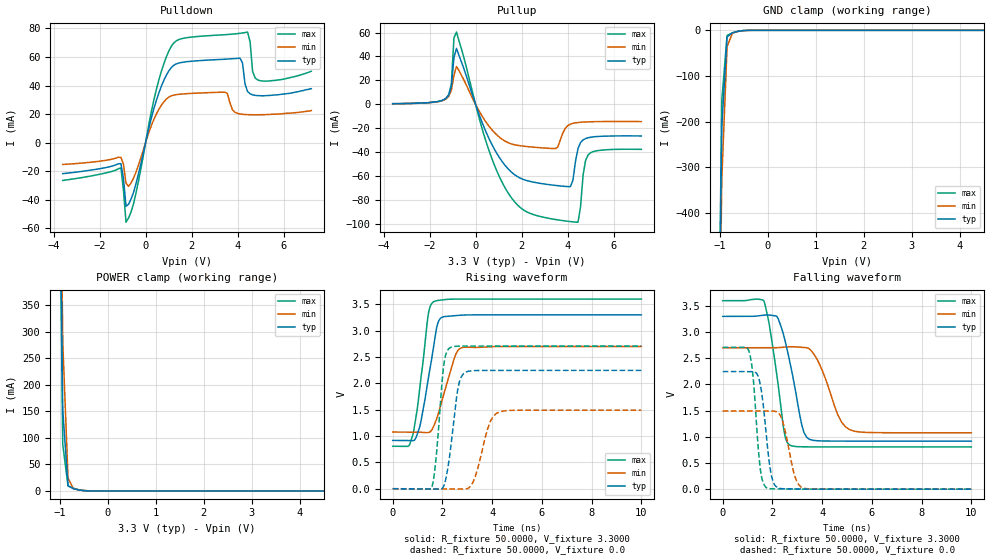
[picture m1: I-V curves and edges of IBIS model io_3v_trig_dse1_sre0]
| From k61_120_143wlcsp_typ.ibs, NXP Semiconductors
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[Model]  io_3v_trig_dse1_sre0
|   Model io_3v_trig_dse1_sre0
| Library cells for typ/min/max conditions are connected as defined below:
|  pad - External Pad
|  ipp_do_3v - Core Input
|  ipp_obe_3v - Output Buffer Enable
|  esd_boost - vdd_s_3v
|  esd_trigger - vss_s_3v
|  ipp_ame_3v - vss_s_3v
|  ipp_dse_3v - vdd_s_3v
|  ipp_ina_3v - NC
|  ipp_ina_mux_3v - NC
|  ipp_ind_3v - NC
|  ipp_pue_3v - vss_s_3v
|  ipp_sre_3v - vss_s_3v
|  tie_3v - vdd_s_3v
|  tie_hi - vdd_s_lv
|  vbuf_3v - vdd_s_3v
|  vdd_s_3v - vdd_s_3v
|  vdd_s_lv - vdd_s_lv
|  vss_bulk - vss_s_3v
|  vss_s_3v - vss_s_3v
| All other pins connected to ground
Model_type I/O
Polarity   Non-Inverting
Enable   Active-High
Vinl =   1.1550V
Vinh =   2.3100V
Vmeas =  1.6500V
Cref =   25.0000pF
Rref =   50.0000
Vref =   0.0V
C_comp   1.9033pF   1.7921pF   2.0562pF
[Temperature Range]   25.0000   0.1250k   -40.0000
[Voltage Range]   3.3000V   2.7000V   3.6000V
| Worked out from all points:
|   slope of the pulldown table from 0 to 0.495 V, typ, clamps not added: 16 ohm
|   slope of the pullup table from 0 to 0.495 V, typ, clamps not added: 19.9 ohm
|   GND clamp passes 1 mA (typ) near -0.54 V on its own axis
|   POWER clamp passes 1 mA (typ) near -0.53 V on its own axis
|   rising waveform, R_fixture 50.0000, V_fixture 3.3000: 20-80 % time 500ps typ, 595ps min, 420ps max; typ from 0.916 V to 3.3 V
|   rising waveform, R_fixture 50.0000, V_fixture 0.0: 20-80 % time 352ps typ, 496ps min, 276ps max; typ from 0 V to 2.25 V
|   falling waveform, R_fixture 50.0000, V_fixture 3.3000: 20-80 % time 594ps typ, 747ps min, 484ps max; typ from 3.3 V to 0.917 V
|   falling waveform, R_fixture 50.0000, V_fixture 0.0: 20-80 % time 311ps typ, 398ps min, 259ps max; typ from 2.25 V to 0 V
[Pulldown]
|Voltage   I(typ)   I(min)   I(max)
-3.6V     -21.69mA   -15.27mA   -26.46mA
-1.07V    -14.69mA   -10.32mA   -17.65mA
-850mV    -44.53mA   -28.35mA   -55.69mA
-520mV    -34.62mA   -24.72mA   -42.62mA
580mV     34.99mA    23.44mA    44.1mA
1.46V     55.81mA    33.87mA    72.31mA
3.44V     58.43mA    35.37mA    75.61mA
4.1V      59.15mA    20.09mA    76.57mA
4.43V     35.88mA    19.6mA     77.43mA
4.65V     33.46mA    19.5mA     49.92mA
4.87V     32.94mA    19.5mA     43.91mA
7.2V      37.8mA     22.5mA     50mA
[Pullup]
|Voltage   I(typ)   I(min)   I(max)
-3.6V     600uA      500uA      600uA
-1.27V    5.28mA     4.76mA     5.35mA
-1.05V    15.3mA     11.87mA    17.35mA
-940mV    39.22mA    24.2mA     55.5mA
-830mV    46.74mA    31.62mA    60.38mA
1.15V     -47.61mA   -29.08mA   -64.99mA
3.24V     -67.13mA   -36.73mA   -95.35mA
4.12V     -68.69mA   -16.52mA   -97.87mA
4.45V     -36.82mA   -15.12mA   -98.37mA
4.78V     -28.52mA   -14.66mA   -46.64mA
5V        -27.41mA   -14.5mA    -40.35mA
7.2V      -26.38mA   -14.35mA   -37.57mA
[GND_clamp]
|Voltage   I(typ)   I(min)   I(max)
-3.6V     -47.82A    -47.1A     -48.34A
-1.07V    -1.102A    -1.183A    -1.105A
-960mV    -210.7mA   -326mA     -154mA
-850mV    -14.47mA   -36.11mA   -11.11mA
-740mV    -5.262mA   -6.035mA   -5.843mA
-520mV    -636.9uA   -916uA     -467.5uA
-300mV    -2.578uA   -18.15uA   -370.9nA
7.2V      0A         0A         0A
[POWER_clamp]
|Voltage   I(typ)   I(min)   I(max)
-3.6V     36.98A     36.74A     37.19A
-1.05V    1.02A      1.161A     949.9mA
-940mV    152.3mA    280.6mA    87.35mA
-830mV    9.987mA    24.48mA    9.181mA
-720mV    4.227mA    4.409mA    5.116mA
-500mV    628.6uA    744.4uA    622.6uA
-390mV    66.57uA    164.1uA    29.9uA
7.2V      0A         0A         0A
[Ramp]
| variable   typ   min   max
dV/dt_r  1.3476/0.3518n   0.8948/0.4962n   1.6250/0.2756n
dV/dt_f  1.4298/0.5936n   0.9745/0.7466n   1.6761/0.4835n
R_load = 50.0000
[Rising Waveform]
R_fixture= 50.0000
V_fixture= 3.3000
V_fixture_min= 2.7000
V_fixture_max= 3.6000
|time   V(typ)   V(min)   V(max)
0s        916.5mV    1.075V     806.1mV
655.6ps   914.3mV    1.075V     817.1mV
816.4ps   912.4mV    1.076V     1.035V
1.097ns   1.192V     1.072V     1.946V
1.408ns   2.029V     1.066V     3.239V
1.649ns   2.723V     1.187V     3.551V
1.904ns   3.226V     1.541V     3.579V
2.479ns   3.283V     2.478V     3.599V
2.753ns   3.294V     2.673V     3.599V
10ns      3.3V       2.7V       3.6V
[Rising Waveform]
R_fixture= 50.0000
V_fixture= 0.0
V_fixture_min= 0.0
V_fixture_max= 0.0
|time   V(typ)   V(min)   V(max)
0s        2.009nV    208.9nV    1.41nV
1.573ns   -4.871mV   -1.881mV   29.97mV
1.723ns   -7.154mV   -2.504mV   480.4mV
2.064ns   65.73mV    -3.393mV   2.383V
2.334ns   784.5mV    -4.35mV    2.683V
2.608ns   1.862V     -4.528mV   2.705V
2.94ns    2.214V     -1.101mV   2.708V
3.306ns   2.243V     211.2mV    2.708V
4.187ns   2.245V     1.435V     2.708V
10ns      2.246V     1.491V     2.708V
[Falling Waveform]
R_fixture= 50.0000
V_fixture= 3.3000
V_fixture_min= 2.7000
V_fixture_max= 3.6000
|time   V(typ)   V(min)   V(max)
0s        3.3V       2.7V       3.6V
1.646ns   3.323V     2.7V       3.603V
2.22ns    3.267V     2.703V     2.032V
2.517ns   2.817V     2.715V     986mV
2.682ns   2.471V     2.72V      846.2mV
3.165ns   1.254V     2.708V     809.3mV
3.49ns    952.4mV    2.676V     808mV
4.627ns   918.4mV    1.423V     806.9mV
5.11ns    917.7mV    1.135V     806.7mV
10ns      917mV      1.076V     806.6mV
[Falling Waveform]
R_fixture= 50.0000
V_fixture= 0.0
V_fixture_min= 0.0
V_fixture_max= 0.0
|time   V(typ)   V(min)   V(max)
0s        2.246V     1.492V     2.709V
1.053ns   2.247V     1.492V     2.643V
1.201ns   2.247V     1.492V     2.25V
1.492ns   2.043V     1.492V     466.6mV
1.756ns   1.018V     1.493V     28.76mV
2.108ns   70.01mV    1.485V     5.423mV
2.385ns   9.554mV    1.335V     3.5mV
2.896ns   4.242mV    251.8mV    676.8uV
3.215ns   1.889mV    24.3mV     444.4uV
10ns      246uV      205.5uV    266.9uV
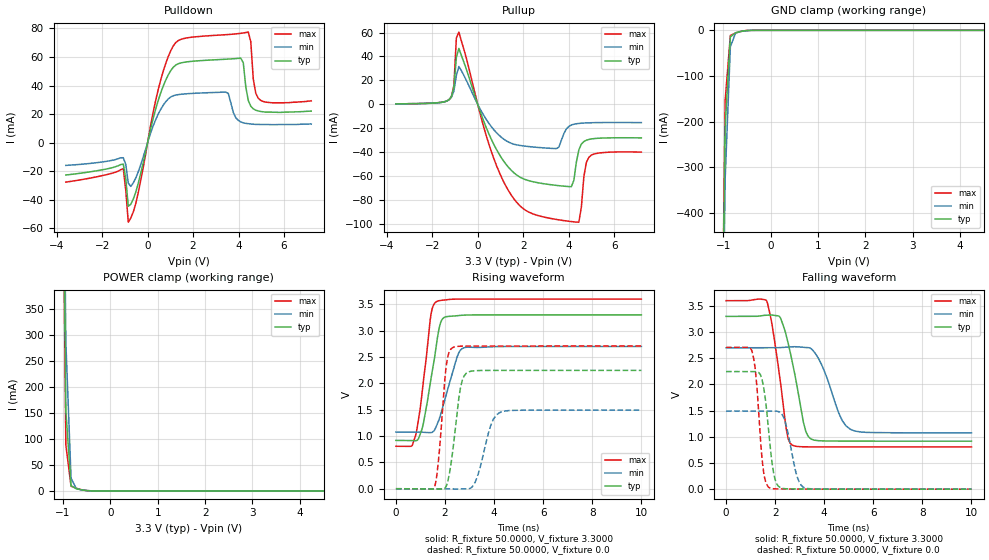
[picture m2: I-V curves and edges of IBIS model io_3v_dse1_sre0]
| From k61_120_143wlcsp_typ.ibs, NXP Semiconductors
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[Model]  io_3v_dse1_sre0
|   Model io_3v_dse1_sre0
| Library cells for typ/min/max conditions are connected as defined below:
|  pad - External Pad
|  ipp_do_3v - Core Input
|  ipp_obe_3v - Output Buffer Enable
|  esd_boost - vdd_s_3v
|  esd_trigger - vss_s_3v
|  ipp_ame_3v - vss_s_3v
|  ipp_dse_3v - vdd_s_3v
|  ipp_ina_3v - NC
|  ipp_ina_mux_3v - NC
|  ipp_ind_3v - NC
|  ipp_pue_3v - vss_s_3v
|  ipp_sre_3v - vss_s_3v
|  tie_3v - vdd_s_3v
|  tie_hi - vdd_s_lv
|  vbuf_3v - vdd_s_3v
|  vdd_s_3v - vdd_s_3v
|  vdd_s_lv - vdd_s_lv
|  vss_bulk - vss_s_3v
|  vss_s_3v - vss_s_3v
| All other pins connected to ground
Model_type I/O
Polarity   Non-Inverting
Enable   Active-High
Vinl =   1.1550V
Vinh =   2.3100V
Vmeas =  1.6500V
Cref =   25.0000pF
Rref =   50.0000
Vref =   0.0V
C_comp   1.9040pF   1.7928pF   2.0571pF
[Temperature Range]   25.0000   0.1250k   -40.0000
[Voltage Range]   3.3000V   2.7000V   3.6000V
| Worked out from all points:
|   slope of the pulldown table from 0 to 0.495 V, typ, clamps not added: 16 ohm
|   slope of the pullup table from 0 to 0.495 V, typ, clamps not added: 19.9 ohm
|   GND clamp passes 1 mA (typ) near -0.54 V on its own axis
|   POWER clamp passes 1 mA (typ) near -0.53 V on its own axis
|   rising waveform, R_fixture 50.0000, V_fixture 3.3000: 20-80 % time 498ps typ, 592ps min, 417ps max; typ from 0.916 V to 3.3 V
|   rising waveform, R_fixture 50.0000, V_fixture 0.0: 20-80 % time 352ps typ, 493ps min, 278ps max; typ from 0 V to 2.25 V
|   falling waveform, R_fixture 50.0000, V_fixture 3.3000: 20-80 % time 593ps typ, 750ps min, 483ps max; typ from 3.3 V to 0.917 V
|   falling waveform, R_fixture 50.0000, V_fixture 0.0: 20-80 % time 309ps typ, 400ps min, 259ps max; typ from 2.25 V to 0 V
[Pulldown]
|Voltage   I(typ)   I(min)   I(max)
-3.6V     -22.64mA   -15.93mA   -27.64mA
-1.07V    -15.06mA   -10.57mA   -18.14mA
-850mV    -44.54mA   -28.36mA   -55.71mA
-520mV    -34.63mA   -24.73mA   -42.63mA
580mV     35mA       23.45mA    44.11mA
1.46V     55.82mA    33.88mA    72.32mA
3.44V     58.43mA    35.37mA    75.62mA
4.1V      59.16mA    14.53mA    76.58mA
4.43V     29.52mA    13.3mA     77.44mA
4.65V     23.68mA    12.9mA     44.58mA
4.87V     22.2mA     12.8mA     31.08mA
7.2V      22.1mA     13mA       29.3mA
[Pullup]
|Voltage   I(typ)   I(min)   I(max)
-3.6V     400uA      400uA      500uA
-1.27V    3.86mA     3.67mA     3.76mA
-1.05V    14.15mA    11.16mA    15.69mA
-940mV    39.2mA     24.13mA    55.51mA
-830mV    46.74mA    31.62mA    60.38mA
1.15V     -47.61mA   -29.08mA   -64.99mA
3.13V     -66.86mA   -36.61mA   -94.95mA
4.12V     -68.7mA    -17.24mA   -97.87mA
4.45V     -37.93mA   -15.9mA    -98.38mA
4.78V     -29.93mA   -15.45mA   -48.43mA
5V        -28.86mA   -15.32mA   -42.37mA
7.2V      -27.98mA   -15.22mA   -39.85mA
[GND_clamp]
|Voltage   I(typ)   I(min)   I(max)
-3.6V     -47.78A    -47.06A    -48.3A
-1.07V    -1.101A    -1.183A    -1.105A
-960mV    -210.7mA   -326mA     -154mA
-850mV    -14.47mA   -36.11mA   -11.11mA
-740mV    -5.262mA   -6.035mA   -5.843mA
-520mV    -637uA     -916uA     -467.5uA
-300mV    -2.578uA   -18.15uA   -370.9nA
7.2V      0A         0A         0A
[POWER_clamp]
|Voltage   I(typ)   I(min)   I(max)
-3.6V     52.51A     51.88A     52.98A
-1.05V    1.126A     1.265A     1.065A
-940mV    154.2mA    286.1mA    88.03mA
-830mV    9.989mA    24.5mA     9.181mA
-720mV    4.227mA    4.409mA    5.116mA
-390mV    66.57uA    164.1uA    29.9uA
7.2V      0A         0A         0A
[Ramp]
| variable   typ   min   max
dV/dt_r  1.3476/0.3516n   0.8948/0.4927n   1.6250/0.2777n
dV/dt_f  1.4299/0.5927n   0.9746/0.7497n   1.6762/0.4828n
R_load = 50.0000
[Rising Waveform]
R_fixture= 50.0000
V_fixture= 3.3000
V_fixture_min= 2.7000
V_fixture_max= 3.6000
|time   V(typ)   V(min)   V(max)
0s        916.3mV    1.075V     805.9mV
621.7ps   914.8mV    1.075V     805.5mV
792.1ps   911.7mV    1.076V     993.8mV
1.076ns   1.155V     1.073V     1.867V
1.43ns    2.093V     1.067V     3.313V
1.67ns    2.797V     1.211V     3.556V
1.907ns   3.229V     1.548V     3.579V
2.497ns   3.284V     2.507V     3.599V
2.749ns   3.294V     2.672V     3.599V
10ns      3.3V       2.7V       3.6V
[Rising Waveform]
R_fixture= 50.0000
V_fixture= 0.0
V_fixture_min= 0.0
V_fixture_max= 0.0
|time   V(typ)   V(min)   V(max)
0s        2.009nV    208.9nV    1.41nV
1.567ns   -4.799mV   -1.781mV   24.52mV
1.753ns   -6.838mV   -2.436mV   626.9mV
2.042ns   42.34mV    -3.404mV   2.304V
2.293ns   631.6mV    -4.18mV    2.673V
2.628ns   1.913V     -4.197mV   2.705V
2.964ns   2.219V     -204.6uV   2.708V
3.255ns   2.241V     151.3mV    2.708V
4.226ns   2.245V     1.445V     2.708V
10ns      2.246V     1.491V     2.708V
[Falling Waveform]
R_fixture= 50.0000
V_fixture= 3.3000
V_fixture_min= 2.7000
V_fixture_max= 3.6000
|time   V(typ)   V(min)   V(max)
0s        3.3V       2.7V       3.6V
1.652ns   3.324V     2.7V       3.6V
1.875ns   3.325V     2.7V       3.141V
2.223ns   3.263V     2.704V     2.02V
2.455ns   2.932V     2.713V     1.136V
2.7ns     2.427V     2.72V      840.5mV
3.149ns   1.285V     2.709V     809.3mV
3.466ns   957mV      2.682V     807.9mV
5.058ns   917.6mV    1.145V     806.6mV
10ns      916.8mV    1.076V     806.4mV
[Falling Waveform]
R_fixture= 50.0000
V_fixture= 0.0
V_fixture_min= 0.0
V_fixture_max= 0.0
|time   V(typ)   V(min)   V(max)
0s        2.246V     1.492V     2.709V
1.042ns   2.247V     1.492V     2.655V
1.236ns   2.244V     1.492V     2.08V
1.465ns   2.096V     1.492V     590mV
1.751ns   1.039V     1.493V     30.59mV
1.932ns   323.6mV    1.494V     8.049mV
2.101ns   74.34mV    1.487V     5.55mV
2.413ns   8.603mV    1.283V     3.29mV
3.2ns     1.968mV    25.81mV    451.3uV
10ns      245.8uV    202.1uV    266.6uV
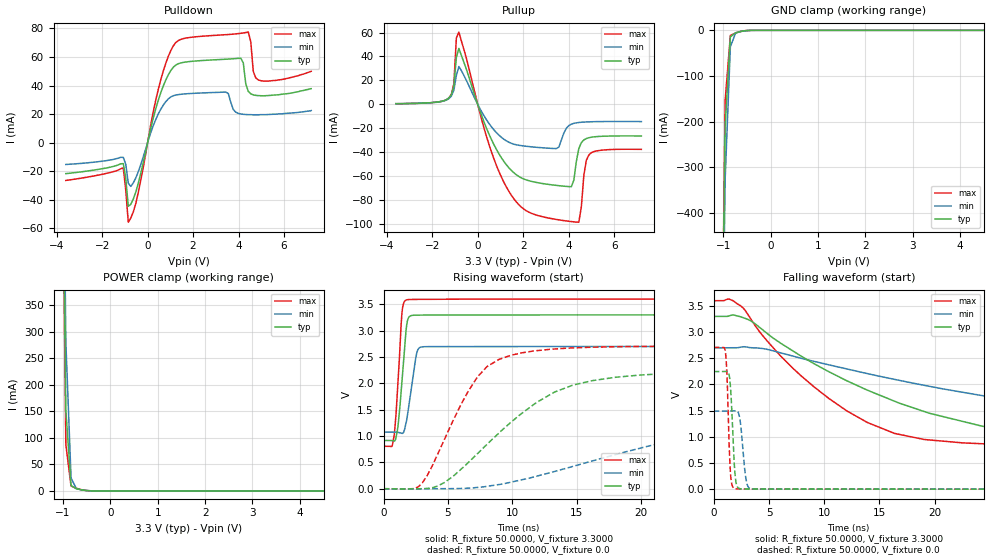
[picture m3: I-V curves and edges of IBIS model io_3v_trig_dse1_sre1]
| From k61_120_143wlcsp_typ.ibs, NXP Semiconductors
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[Model]  io_3v_trig_dse1_sre1
|   Model io_3v_trig_dse1_sre1
| Library cells for typ/min/max conditions are connected as defined below:
|  pad - External Pad
|  ipp_do_3v - Core Input
|  ipp_obe_3v - Output Buffer Enable
|  esd_boost - vdd_s_3v
|  esd_trigger - vss_s_3v
|  ipp_ame_3v - vss_s_3v
|  ipp_dse_3v - vdd_s_3v
|  ipp_ina_3v - NC
|  ipp_ina_mux_3v - NC
|  ipp_ind_3v - NC
|  ipp_pue_3v - vss_s_3v
|  ipp_sre_3v - vdd_s_3v
|  tie_3v - vdd_s_3v
|  tie_hi - vdd_s_lv
|  vbuf_3v - vdd_s_3v
|  vdd_s_3v - vdd_s_3v
|  vdd_s_lv - vdd_s_lv
|  vss_bulk - vss_s_3v
|  vss_s_3v - vss_s_3v
| All other pins connected to ground
Model_type I/O
Polarity   Non-Inverting
Enable   Active-High
Vinl =   1.1550V
Vinh =   2.3100V
Vmeas =  1.6500V
Cref =   25.0000pF
Rref =   50.0000
Vref =   0.0V
C_comp   1.9033pF   1.7921pF   2.0562pF
[Temperature Range]   25.0000   0.1250k   -40.0000
[Voltage Range]   3.3000V   2.7000V   3.6000V
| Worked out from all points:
|   slope of the pulldown table from 0 to 0.495 V, typ, clamps not added: 16 ohm
|   slope of the pullup table from 0 to 0.495 V, typ, clamps not added: 19.9 ohm
|   GND clamp passes 1 mA (typ) near -0.54 V on its own axis
|   POWER clamp passes 1 mA (typ) near -0.53 V on its own axis
|   rising waveform, R_fixture 50.0000, V_fixture 3.3000: 20-80 % time 477ps typ, 574ps min, 395ps max; typ from 0.916 V to 3.3 V
|   rising waveform, R_fixture 50.0000, V_fixture 0.0: 20-80 % time 6.64ns typ, 16ns min, 3.47ns max; typ from 0 V to 2.25 V
|   falling waveform, R_fixture 50.0000, V_fixture 3.3000: 20-80 % time 14.8ns typ, 28.6ns min, 9.11ns max; typ from 3.3 V to 0.916 V
|   falling waveform, R_fixture 50.0000, V_fixture 0.0: 20-80 % time 304ps typ, 395ps min, 253ps max; typ from 2.25 V to 0 V
[Pulldown]
|Voltage   I(typ)   I(min)   I(max)
-3.6V     -21.69mA   -15.27mA   -26.46mA
-1.07V    -14.69mA   -10.32mA   -17.65mA
-850mV    -44.53mA   -28.35mA   -55.69mA
-520mV    -34.62mA   -24.72mA   -42.62mA
580mV     34.99mA    23.44mA    44.1mA
1.46V     55.81mA    33.87mA    72.31mA
3.44V     58.43mA    35.36mA    75.61mA
4.1V      59.15mA    20.09mA    76.57mA
4.43V     35.88mA    19.6mA     77.43mA
4.65V     33.46mA    19.5mA     49.92mA
4.87V     32.94mA    19.5mA     43.91mA
7.2V      37.8mA     22.5mA     50mA
[Pullup]
|Voltage   I(typ)   I(min)   I(max)
-3.6V     600uA      500uA      600uA
-1.27V    5.28mA     4.76mA     5.35mA
-1.05V    15.3mA     11.87mA    17.35mA
-940mV    39.22mA    24.2mA     55.5mA
-830mV    46.74mA    31.62mA    60.38mA
1.15V     -47.61mA   -29.08mA   -64.99mA
3.24V     -67.13mA   -36.73mA   -95.35mA
4.12V     -68.69mA   -16.52mA   -97.87mA
4.45V     -36.82mA   -15.12mA   -98.37mA
4.78V     -28.52mA   -14.66mA   -46.64mA
5V        -27.41mA   -14.5mA    -40.35mA
7.2V      -26.38mA   -14.35mA   -37.57mA
[GND_clamp]
|Voltage   I(typ)   I(min)   I(max)
-3.6V     -47.82A    -47.1A     -48.34A
-1.07V    -1.102A    -1.183A    -1.105A
-960mV    -210.7mA   -326mA     -154mA
-850mV    -14.47mA   -36.11mA   -11.11mA
-740mV    -5.262mA   -6.035mA   -5.843mA
-520mV    -636.9uA   -916uA     -467.5uA
-300mV    -2.578uA   -18.15uA   -370.9nA
7.2V      0A         0A         0A
[POWER_clamp]
|Voltage   I(typ)   I(min)   I(max)
-3.6V     36.98A     36.74A     37.19A
-1.05V    1.02A      1.161A     949.9mA
-940mV    152.3mA    280.6mA    87.35mA
-830mV    9.987mA    24.48mA    9.181mA
-720mV    4.227mA    4.409mA    5.116mA
-500mV    628.6uA    744.4uA    622.6uA
-390mV    66.57uA    164.1uA    29.9uA
7.2V      0A         0A         0A
[Ramp]
| variable   typ   min   max
dV/dt_r  1.3478/6.6433n   0.8951/15.9651n   1.6252/3.4740n
dV/dt_f  1.4301/14.8115n   0.9748/28.5903n   1.6764/9.1110n
R_load = 50.0000
[Rising Waveform]
R_fixture= 50.0000
V_fixture= 3.3000
V_fixture_min= 2.7000
V_fixture_max= 3.6000
|time   V(typ)   V(min)   V(max)
0s        916.5mV    1.075V     806.1mV
650.6ps   913mV      1.075V     805mV
931.5ps   941.1mV    1.075V     1.321V
1.123ns   1.202V     1.069V     2.075V
1.446ns   2.116V     1.05V      3.391V
1.777ns   3.084V     1.287V     3.584V
2.039ns   3.275V     1.715V     3.592V
2.624ns   3.295V     2.618V     3.594V
3.319ns   3.296V     2.697V     3.596V
250ns     3.3V       2.7V       3.6V
[Rising Waveform]
R_fixture= 50.0000
V_fixture= 0.0
V_fixture_min= 0.0
V_fixture_max= 0.0
|time   V(typ)   V(min)   V(max)
0s        2.009nV    208.9nV    1.41nV
3.009ns   -219.1uV   -587uV     112mV
4.711ns   115.5mV    -134.9uV   928.5mV
6.575ns   496.1mV    10.62mV    1.85V
8.035ns   842.2mV    45.24mV    2.318V
11.88ns   1.637V     236.6mV    2.62V
14.36ns   1.934V     399.2mV    2.669V
28.19ns   2.227V     1.175V     2.708V
47.72ns   2.246V     1.454V     2.709V
250ns     2.246V     1.492V     2.709V
[Falling Waveform]
R_fixture= 50.0000
V_fixture= 3.3000
V_fixture_min= 2.7000
V_fixture_max= 3.6000
|time   V(typ)   V(min)   V(max)
0s        3.3V       2.7V       3.6V
2.461ns   3.291V     2.714V     3.498V
7.044ns   2.656V     2.549V     2.333V
12.05ns   2.07V      2.296V     1.495V
16.36ns   1.681V     2.098V     1.065V
22.52ns   1.295V     1.851V     884.6mV
33.62ns   1V         1.512V     822.6mV
50.17ns   932.6mV    1.236V     808.3mV
68.28ns   919.6mV    1.128V     806.3mV
250ns     916.5mV    1.075V     806.1mV
[Falling Waveform]
R_fixture= 50.0000
V_fixture= 0.0
V_fixture_min= 0.0
V_fixture_max= 0.0
|time   V(typ)   V(min)   V(max)
0s        2.246V     1.492V     2.709V
1.039ns   2.248V     1.492V     2.646V
1.215ns   2.248V     1.491V     2.075V
1.383ns   2.193V     1.492V     904.8mV
1.579ns   1.732V     1.493V     152.8mV
1.894ns   356.7mV    1.497V     10.97mV
2.096ns   61.58mV    1.493V     5.077mV
2.977ns   3.283mV    126.5mV    1.844mV
3.602ns   1.859mV    3.488mV    1.169mV
250ns     -5.291nV   200.6nV    -4.024nV
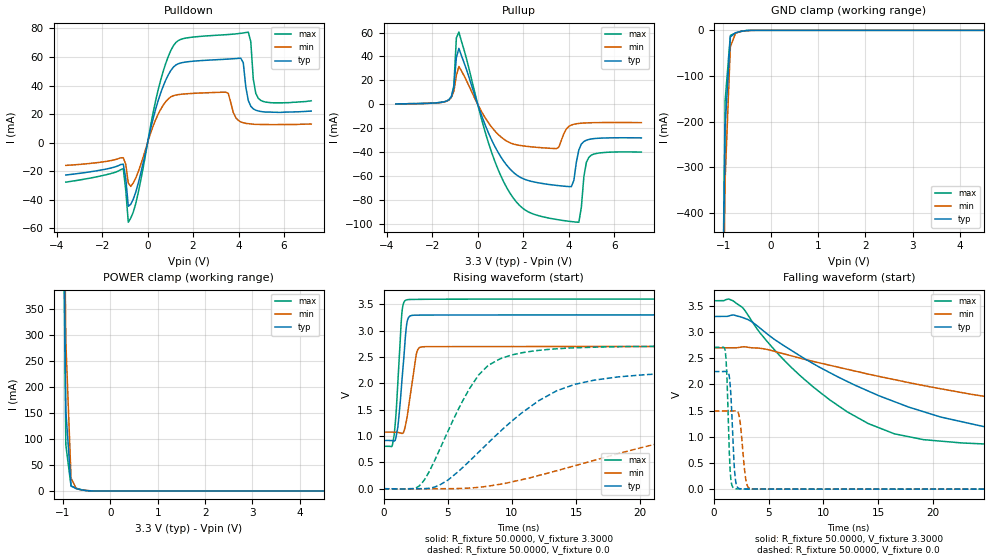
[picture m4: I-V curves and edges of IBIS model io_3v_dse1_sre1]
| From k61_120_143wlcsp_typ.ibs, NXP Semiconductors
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[Model]  io_3v_dse1_sre1
|   Model io_3v_dse1_sre1
| Library cells for typ/min/max conditions are connected as defined below:
|  pad - External Pad
|  ipp_do_3v - Core Input
|  ipp_obe_3v - Output Buffer Enable
|  esd_boost - vdd_s_3v
|  esd_trigger - vss_s_3v
|  ipp_ame_3v - vss_s_3v
|  ipp_dse_3v - vdd_s_3v
|  ipp_ina_3v - NC
|  ipp_ina_mux_3v - NC
|  ipp_ind_3v - NC
|  ipp_pue_3v - vss_s_3v
|  ipp_sre_3v - vdd_s_3v
|  tie_3v - vdd_s_3v
|  tie_hi - vdd_s_lv
|  vbuf_3v - vdd_s_3v
|  vdd_s_3v - vdd_s_3v
|  vdd_s_lv - vdd_s_lv
|  vss_bulk - vss_s_3v
|  vss_s_3v - vss_s_3v
| All other pins connected to ground
Model_type I/O
Polarity   Non-Inverting
Enable   Active-High
Vinl =   1.1550V
Vinh =   2.3100V
Vmeas =  1.6500V
Cref =   25.0000pF
Rref =   50.0000
Vref =   0.0V
C_comp   1.9040pF   1.7928pF   2.0571pF
[Temperature Range]   25.0000   0.1250k   -40.0000
[Voltage Range]   3.3000V   2.7000V   3.6000V
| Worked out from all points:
|   slope of the pulldown table from 0 to 0.495 V, typ, clamps not added: 16 ohm
|   slope of the pullup table from 0 to 0.495 V, typ, clamps not added: 19.9 ohm
|   GND clamp passes 1 mA (typ) near -0.54 V on its own axis
|   POWER clamp passes 1 mA (typ) near -0.53 V on its own axis
|   rising waveform, R_fixture 50.0000, V_fixture 3.3000: 20-80 % time 474ps typ, 573ps min, 392ps max; typ from 0.916 V to 3.3 V
|   rising waveform, R_fixture 50.0000, V_fixture 0.0: 20-80 % time 6.66ns typ, 16ns min, 3.45ns max; typ from 0 V to 2.25 V
|   falling waveform, R_fixture 50.0000, V_fixture 3.3000: 20-80 % time 14.7ns typ, 28.4ns min, 9.12ns max; typ from 3.3 V to 0.916 V
|   falling waveform, R_fixture 50.0000, V_fixture 0.0: 20-80 % time 303ps typ, 390ps min, 251ps max; typ from 2.25 V to 0 V
[Pulldown]
|Voltage   I(typ)   I(min)   I(max)
-3.6V     -22.64mA   -15.93mA   -27.64mA
-1.07V    -15.06mA   -10.57mA   -18.14mA
-850mV    -44.54mA   -28.36mA   -55.71mA
-520mV    -34.63mA   -24.73mA   -42.63mA
580mV     35mA       23.45mA    44.11mA
1.46V     55.82mA    33.87mA    72.32mA
3.44V     58.43mA    35.37mA    75.62mA
4.1V      59.16mA    14.52mA    76.58mA
4.43V     29.52mA    13.3mA     77.44mA
4.65V     23.68mA    12.9mA     44.58mA
4.87V     22.2mA     12.8mA     31.08mA
7.2V      22.1mA     13mA       29.3mA
[Pullup]
|Voltage   I(typ)   I(min)   I(max)
-3.6V     400uA      400uA      500uA
-1.27V    3.86mA     3.67mA     3.76mA
-1.05V    14.15mA    11.16mA    15.69mA
-940mV    39.2mA     24.13mA    55.51mA
-830mV    46.74mA    31.62mA    60.38mA
1.15V     -47.61mA   -29.08mA   -64.99mA
3.13V     -66.86mA   -36.61mA   -94.95mA
4.12V     -68.7mA    -17.24mA   -97.87mA
4.45V     -37.93mA   -15.9mA    -98.38mA
4.78V     -29.93mA   -15.45mA   -48.43mA
5V        -28.86mA   -15.31mA   -42.37mA
7.2V      -27.98mA   -15.22mA   -39.85mA
[GND_clamp]
|Voltage   I(typ)   I(min)   I(max)
-3.6V     -47.78A    -47.06A    -48.3A
-1.07V    -1.101A    -1.183A    -1.105A
-960mV    -210.7mA   -326mA     -154mA
-850mV    -14.47mA   -36.11mA   -11.11mA
-740mV    -5.262mA   -6.035mA   -5.843mA
-520mV    -637uA     -916uA     -467.5uA
-300mV    -2.578uA   -18.15uA   -370.9nA
7.2V      0A         0A         0A
[POWER_clamp]
|Voltage   I(typ)   I(min)   I(max)
-3.6V     52.51A     51.88A     52.98A
-1.05V    1.126A     1.265A     1.065A
-940mV    154.2mA    286.1mA    88.03mA
-830mV    9.989mA    24.5mA     9.181mA
-720mV    4.227mA    4.409mA    5.116mA
-390mV    66.57uA    164.1uA    29.9uA
7.2V      0A         0A         0A
[Ramp]
| variable   typ   min   max
dV/dt_r  1.3478/6.6600n   0.8951/16.0012n   1.6252/3.4473n
dV/dt_f  1.4302/14.6691n   0.9749/28.4435n   1.6765/9.1203n
R_load = 50.0000
[Rising Waveform]
R_fixture= 50.0000
V_fixture= 3.3000
V_fixture_min= 2.7000
V_fixture_max= 3.6000
|time   V(typ)   V(min)   V(max)
0s        916.3mV    1.075V     805.9mV
678.6ps   911.9mV    1.076V     821.6mV
948.9ps   960.7mV    1.075V     1.368V
1.142ns   1.248V     1.069V     2.149V
1.44ns    2.104V     1.048V     3.383V
1.773ns   3.082V     1.282V     3.584V
2.015ns   3.271V     1.675V     3.592V
2.591ns   3.295V     2.594V     3.594V
3.273ns   3.296V     2.696V     3.596V
250ns     3.3V       2.7V       3.6V
[Rising Waveform]
R_fixture= 50.0000
V_fixture= 0.0
V_fixture_min= 0.0
V_fixture_max= 0.0
|time   V(typ)   V(min)   V(max)
0s        2.009nV    208.9nV    1.41nV
2.888ns   -686.6uV   -942.1uV   78.44mV
5.004ns   162.9mV    201.7uV    1.087V
6.684ns   521.6mV    12.22mV    1.896V
8.154ns   871mV      49.22mV    2.341V
12.1ns    1.672V     250.4mV    2.626V
14.44ns   1.941V     405.3mV    2.67V
27.7ns    2.225V     1.157V     2.708V
46.86ns   2.246V     1.45V      2.709V
250ns     2.246V     1.492V     2.709V
[Falling Waveform]
R_fixture= 50.0000
V_fixture= 3.3000
V_fixture_min= 2.7000
V_fixture_max= 3.6000
|time   V(typ)   V(min)   V(max)
0s        3.3V       2.7V       3.6V
1.383ns   3.309V     2.7V       3.631V
2.462ns   3.291V     2.714V     3.497V
7.003ns   2.661V     2.551V     2.34V
12.17ns   2.058V     2.289V     1.478V
16.47ns   1.673V     2.093V     1.058V
22.63ns   1.288V     1.846V     883.1mV
34.5ns    992.2mV    1.491V     821mV
65.83ns   920.4mV    1.137V     806.1mV
250ns     916.3mV    1.075V     805.9mV
[Falling Waveform]
R_fixture= 50.0000
V_fixture= 0.0
V_fixture_min= 0.0
V_fixture_max= 0.0
|time   V(typ)   V(min)   V(max)
0s        2.246V     1.492V     2.709V
1.03ns    2.248V     1.492V     2.658V
1.2ns     2.248V     1.491V     2.159V
1.392ns   2.184V     1.492V     849.6mV
1.608ns   1.619V     1.493V     116.7mV
1.837ns   544.9mV    1.496V     16.25mV
2.079ns   71.93mV    1.495V     5.402mV
2.932ns   3.505mV    173.4mV    1.976mV
3.597ns   1.905mV    3.625mV    1.19mV
250ns     -5.298nV   200.5nV    -4.023nV
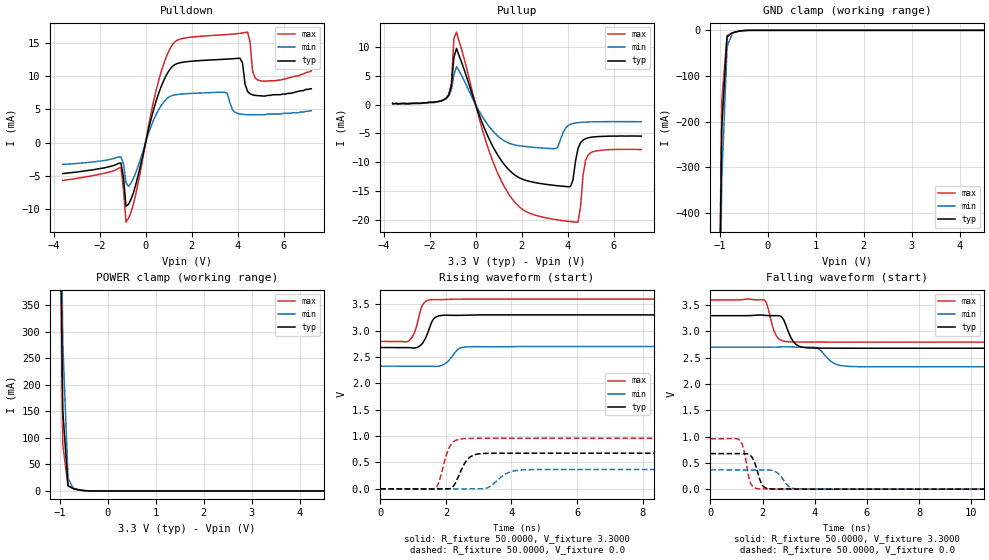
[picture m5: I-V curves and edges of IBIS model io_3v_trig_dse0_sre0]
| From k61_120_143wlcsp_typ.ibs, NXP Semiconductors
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[Model]  io_3v_trig_dse0_sre0
|   Model io_3v_trig_dse0_sre0
| Library cells for typ/min/max conditions are connected as defined below:
|  pad - External Pad
|  ipp_do_3v - Core Input
|  ipp_obe_3v - Output Buffer Enable
|  esd_boost - vdd_s_3v
|  esd_trigger - vss_s_3v
|  ipp_ame_3v - vss_s_3v
|  ipp_dse_3v - vss_s_3v
|  ipp_ina_3v - NC
|  ipp_ina_mux_3v - NC
|  ipp_ind_3v - NC
|  ipp_pue_3v - vss_s_3v
|  ipp_sre_3v - vss_s_3v
|  tie_3v - vdd_s_3v
|  tie_hi - vdd_s_lv
|  vbuf_3v - vdd_s_3v
|  vdd_s_3v - vdd_s_3v
|  vdd_s_lv - vdd_s_lv
|  vss_bulk - vss_s_3v
|  vss_s_3v - vss_s_3v
| All other pins connected to ground
Model_type I/O
Polarity   Non-Inverting
Enable   Active-High
Vinl =   1.1550V
Vinh =   2.3100V
Vmeas =  1.6500V
Cref =   25.0000pF
Rref =   50.0000
Vref =   0.0V
C_comp   1.9033pF   1.7921pF   2.0562pF
[Temperature Range]   25.0000   0.1250k   -40.0000
[Voltage Range]   3.3000V   2.7000V   3.6000V
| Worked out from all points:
|   slope of the pulldown table from 0 to 0.495 V, typ, clamps not added: 74.6 ohm
|   slope of the pullup table from 0 to 0.495 V, typ, clamps not added: 96.1 ohm
|   GND clamp passes 1 mA (typ) near -0.54 V on its own axis
|   POWER clamp passes 1 mA (typ) near -0.53 V on its own axis
|   rising waveform, R_fixture 50.0000, V_fixture 3.3000: 20-80 % time 249ps typ, 295ps min, 218ps max; typ from 2.68 V to 3.3 V
|   rising waveform, R_fixture 50.0000, V_fixture 0.0: 20-80 % time 324ps typ, 446ps min, 273ps max; typ from 0 V to 0.676 V
|   falling waveform, R_fixture 50.0000, V_fixture 3.3000: 20-80 % time 336ps typ, 464ps min, 278ps max; typ from 3.3 V to 2.68 V
|   falling waveform, R_fixture 50.0000, V_fixture 0.0: 20-80 % time 264ps typ, 346ps min, 219ps max; typ from 0.676 V to 0 V
[Pulldown]
|Voltage   I(typ)   I(min)   I(max)
-3.6V     -4.64mA    -3.27mA    -5.68mA
-1.07V    -3.05mA    -2.138mA   -3.686mA
-850mV    -9.531mA   -6.04mA    -11.94mA
-520mV    -7.433mA   -5.304mA   -9.157mA
580mV     7.512mA    5.028mA    9.473mA
1.46V     11.97mA    7.26mA     15.51mA
3.44V     12.53mA    7.58mA     16.21mA
4.1V      12.68mA    4.3mA      16.42mA
4.43V     7.69mA     4.2mA      16.6mA
4.65V     7.17mA     4.2mA      10.69mA
4.87V     7.06mA     4.2mA      9.41mA
7.2V      8.1mA      4.8mA      10.8mA
[Pullup]
|Voltage   I(typ)   I(min)   I(max)
-3.6V     200uA      100uA      200uA
-1.27V    1.12mA     1.01mA     1.13mA
-1.05V    3.27mA     2.54mA     3.696mA
-940mV    8.16mA     5.079mA    11.47mA
-830mV    9.694mA    6.562mA    12.52mA
1.15V     -9.866mA   -6.026mA   -13.47mA
3.24V     -13.9mA    -7.609mA   -19.73mA
4.12V     -14.22mA   -3.42mA    -20.25mA
4.45V     -7.608mA   -3.13mA    -20.35mA
4.78V     -5.902mA   -3.04mA    -9.632mA
5V        -5.67mA    -3mA       -8.343mA
7.2V      -5.46mA    -2.98mA    -7.78mA
[GND_clamp]
|Voltage   I(typ)   I(min)   I(max)
-3.6V     -47.82A    -47.1A     -48.34A
-1.07V    -1.102A    -1.183A    -1.105A
-960mV    -210.7mA   -326mA     -154mA
-850mV    -14.47mA   -36.11mA   -11.11mA
-740mV    -5.262mA   -6.035mA   -5.843mA
-520mV    -636.9uA   -916uA     -467.5uA
-300mV    -2.578uA   -18.15uA   -370.9nA
7.2V      0A         0A         0A
[POWER_clamp]
|Voltage   I(typ)   I(min)   I(max)
-3.6V     36.98A     36.74A     37.19A
-1.05V    1.02A      1.161A     949.9mA
-940mV    152.3mA    280.6mA    87.35mA
-830mV    9.987mA    24.48mA    9.181mA
-720mV    4.227mA    4.409mA    5.116mA
-500mV    628.6uA    744.4uA    622.6uA
-390mV    66.57uA    164.1uA    29.9uA
7.2V      0A         0A         0A
[Ramp]
| variable   typ   min   max
dV/dt_r  0.4057/0.3234n   0.2199/0.4457n   0.5756/0.2727n
dV/dt_f  0.3715/0.3360n   0.2234/0.4635n   0.4821/0.2780n
R_load = 50.0000
[Rising Waveform]
R_fixture= 50.0000
V_fixture= 3.3000
V_fixture_min= 2.7000
V_fixture_max= 3.6000
|time   V(typ)   V(min)   V(max)
0s        2.681V     2.328V     2.796V
881.7ps   2.678V     2.328V     2.812V
1.026ns   2.672V     2.328V     2.94V
1.299ns   2.77V      2.327V     3.498V
1.593ns   3.192V     2.322V     3.59V
1.709ns   3.263V     2.321V     3.588V
1.932ns   3.292V     2.355V     3.589V
2.402ns   3.291V     2.661V     3.599V
2.708ns   3.297V     2.696V     3.599V
20ns      3.3V       2.7V       3.6V
[Rising Waveform]
R_fixture= 50.0000
V_fixture= 0.0
V_fixture_min= 0.0
V_fixture_max= 0.0
|time   V(typ)   V(min)   V(max)
0s        5.332nV    489.5nV    4.027nV
1.688ns   -2.656mV   -95.5uV    13.65mV
2.13ns    5.672mV    -2.28mV    818.1mV
2.511ns   412.6mV    -1.555mV   950.9mV
2.73ns    601.7mV    -468.2uV   956.6mV
2.994ns   663.2mV    -701.5uV   958.2mV
3.338ns   674.2mV    40.47mV    958.6mV
3.908ns   675.6mV    309.8mV    958.8mV
4.482ns   675.8mV    363.1mV    958.9mV
20ns      676.2mV    366.5mV    959.4mV
[Falling Waveform]
R_fixture= 50.0000
V_fixture= 3.3000
V_fixture_min= 2.7000
V_fixture_max= 3.6000
|time   V(typ)   V(min)   V(max)
0s        3.3V       2.7V       3.6V
2.059ns   3.307V     2.7V       3.599V
2.542ns   3.3V       2.703V     2.907V
2.728ns   3.282V     2.705V     2.829V
3.008ns   2.971V     2.708V     2.803V
3.41ns    2.715V     2.701V     2.799V
4.115ns   2.683V     2.681V     2.797V
4.675ns   2.682V     2.412V     2.797V
5.235ns   2.681V     2.337V     2.797V
20ns      2.681V     2.328V     2.796V
[Falling Waveform]
R_fixture= 50.0000
V_fixture= 0.0
V_fixture_min= 0.0
V_fixture_max= 0.0
|time   V(typ)   V(min)   V(max)
0s        676.3mV    366.6mV    959.6mV
1.138ns   677.2mV    366.5mV    928.2mV
1.283ns   677.9mV    366.6mV    754.8mV
1.523ns   647.2mV    366.7mV    138.4mV
1.847ns   266.1mV    367.2mV    7.41mV
2.138ns   20.01mV    367.8mV    5.162mV
2.459ns   2.457mV    344.2mV    2.105mV
2.977ns   3.014mV    61.18mV    486.5uV
3.371ns   642.7uV    2.922mV    417.4uV
20ns      97.17uV    59.07uV    132.2uV
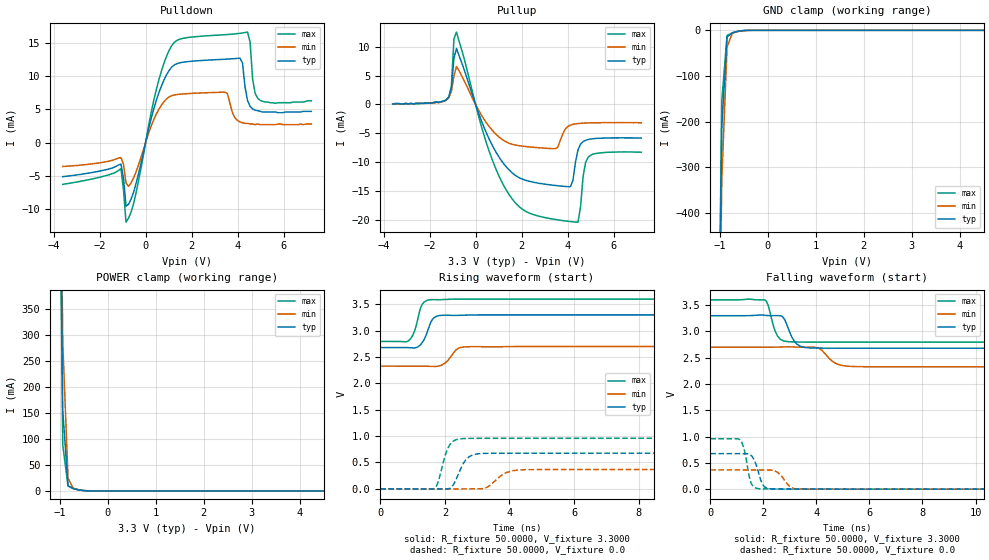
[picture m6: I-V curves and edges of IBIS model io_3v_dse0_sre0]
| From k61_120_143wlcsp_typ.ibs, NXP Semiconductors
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[Model]  io_3v_dse0_sre0
|   Model io_3v_dse0_sre0
| Library cells for typ/min/max conditions are connected as defined below:
|  pad - External Pad
|  ipp_do_3v - Core Input
|  ipp_obe_3v - Output Buffer Enable
|  esd_boost - vdd_s_3v
|  esd_trigger - vss_s_3v
|  ipp_ame_3v - vss_s_3v
|  ipp_dse_3v - vss_s_3v
|  ipp_ina_3v - NC
|  ipp_ina_mux_3v - NC
|  ipp_ind_3v - NC
|  ipp_pue_3v - vss_s_3v
|  ipp_sre_3v - vss_s_3v
|  tie_3v - vdd_s_3v
|  tie_hi - vdd_s_lv
|  vbuf_3v - vdd_s_3v
|  vdd_s_3v - vdd_s_3v
|  vdd_s_lv - vdd_s_lv
|  vss_bulk - vss_s_3v
|  vss_s_3v - vss_s_3v
| All other pins connected to ground
Model_type I/O
Polarity   Non-Inverting
Enable   Active-High
Vinl =   1.1550V
Vinh =   2.3100V
Vmeas =  1.6500V
Cref =   25.0000pF
Rref =   50.0000
Vref =   0.0V
C_comp   1.9040pF   1.7928pF   2.0571pF
[Temperature Range]   25.0000   0.1250k   -40.0000
[Voltage Range]   3.3000V   2.7000V   3.6000V
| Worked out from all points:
|   slope of the pulldown table from 0 to 0.495 V, typ, clamps not added: 74.6 ohm
|   slope of the pullup table from 0 to 0.495 V, typ, clamps not added: 96.1 ohm
|   GND clamp passes 1 mA (typ) near -0.54 V on its own axis
|   POWER clamp passes 1 mA (typ) near -0.53 V on its own axis
|   rising waveform, R_fixture 50.0000, V_fixture 3.3000: 20-80 % time 244ps typ, 298ps min, 217ps max; typ from 2.68 V to 3.3 V
|   rising waveform, R_fixture 50.0000, V_fixture 0.0: 20-80 % time 323ps typ, 445ps min, 270ps max; typ from 0 V to 0.676 V
|   falling waveform, R_fixture 50.0000, V_fixture 3.3000: 20-80 % time 337ps typ, 465ps min, 278ps max; typ from 3.3 V to 2.68 V
|   falling waveform, R_fixture 50.0000, V_fixture 0.0: 20-80 % time 258ps typ, 351ps min, 218ps max; typ from 0.676 V to 0 V
[Pulldown]
|Voltage   I(typ)   I(min)   I(max)
-3.6V     -5.11mA    -3.58mA    -6.26mA
-1.07V    -3.221mA   -2.25mA    -3.914mA
-850mV    -9.536mA   -6.048mA   -11.95mA
-520mV    -7.435mA   -5.305mA   -9.159mA
580mV     7.513mA    5.029mA    9.475mA
1.46V     11.97mA    7.26mA     15.51mA
3.44V     12.53mA    7.581mA    16.21mA
4.1V      12.68mA    3.11mA     16.42mA
4.43V     6.32mA     2.9mA      16.6mA
4.65V     5.07mA     2.8mA      9.53mA
4.87V     4.8mA      2.8mA      6.66mA
7.2V      4.7mA      2.8mA      6.3mA
[Pullup]
|Voltage   I(typ)   I(min)   I(max)
-3.6V     100uA      100uA      100uA
-1.27V    830uA      760uA      820uA
-1.05V    2.86mA     2.26mA     3.17mA
-940mV    8.013mA    4.943mA    11.33mA
-830mV    9.687mA    6.548mA    12.52mA
710mV     -6.946mA   -4.399mA   -9.402mA
2.14V     -13.06mA   -7.25mA    -18.39mA
3.46V     -14mA      -7.642mA   -19.88mA
4.12V     -14.22mA   -3.569mA   -20.25mA
4.45V     -7.839mA   -3.29mA    -20.35mA
4.89V     -6.059mA   -3.18mA    -9.139mA
7.2V      -5.79mA    -3.15mA    -8.25mA
[GND_clamp]
|Voltage   I(typ)   I(min)   I(max)
-3.6V     -47.78A    -47.06A    -48.3A
-1.07V    -1.101A    -1.183A    -1.105A
-960mV    -210.7mA   -326mA     -154mA
-850mV    -14.47mA   -36.11mA   -11.11mA
-740mV    -5.262mA   -6.035mA   -5.843mA
-520mV    -637uA     -916uA     -467.5uA
-300mV    -2.578uA   -18.15uA   -370.9nA
7.2V      0A         0A         0A
[POWER_clamp]
|Voltage   I(typ)   I(min)   I(max)
-3.6V     52.51A     51.88A     52.98A
-1.05V    1.126A     1.265A     1.065A
-940mV    154.2mA    286.1mA    88.03mA
-830mV    9.989mA    24.5mA     9.181mA
-720mV    4.227mA    4.409mA    5.116mA
-390mV    66.57uA    164.1uA    29.9uA
7.2V      0A         0A         0A
[Ramp]
| variable   typ   min   max
dV/dt_r  0.4057/0.3226n   0.2199/0.4455n   0.5756/0.2700n
dV/dt_f  0.3715/0.3371n   0.2234/0.4654n   0.4821/0.2777n
R_load = 50.0000
[Rising Waveform]
R_fixture= 50.0000
V_fixture= 3.3000
V_fixture_min= 2.7000
V_fixture_max= 3.6000
|time   V(typ)   V(min)   V(max)
0s        2.681V     2.328V     2.796V
899.8ps   2.677V     2.328V     2.822V
1.069ns   2.674V     2.328V     3.007V
1.285ns   2.765V     2.327V     3.484V
1.54ns    3.124V     2.323V     3.587V
1.786ns   3.281V     2.326V     3.587V
2ns       3.294V     2.382V     3.592V
2.358ns   3.29V      2.643V     3.599V
2.716ns   3.297V     2.696V     3.599V
20ns      3.3V       2.7V       3.6V
[Rising Waveform]
R_fixture= 50.0000
V_fixture= 0.0
V_fixture_min= 0.0
V_fixture_max= 0.0
|time   V(typ)   V(min)   V(max)
0s        5.331nV    489.5nV    4.026nV
1.674ns   -2.924mV   -74.12uV   6.896mV
1.761ns   -1.492mV   -281.9uV   81.95mV
2.013ns   -1.23mV    -1.415mV   642.6mV
2.158ns   11.49mV    -2.502mV   843.1mV
2.538ns   442.5mV    -1.27mV    952.1mV
2.893ns   650.2mV    -582.6uV   957.8mV
3.9ns     675.5mV    307.7mV    958.7mV
4.466ns   675.7mV    362.8mV    958.8mV
20ns      676.1mV    366.5mV    959.4mV
[Falling Waveform]
R_fixture= 50.0000
V_fixture= 3.3000
V_fixture_min= 2.7000
V_fixture_max= 3.6000
|time   V(typ)   V(min)   V(max)
0s        3.3V       2.7V       3.6V
2.061ns   3.307V     2.7V       3.599V
2.537ns   3.3V       2.703V     2.911V
2.725ns   3.283V     2.705V     2.83V
2.991ns   2.992V     2.708V     2.804V
3.417ns   2.714V     2.701V     2.799V
4.067ns   2.684V     2.689V     2.797V
4.756ns   2.682V     2.386V     2.797V
5.39ns    2.681V     2.333V     2.797V
20ns      2.681V     2.328V     2.796V
[Falling Waveform]
R_fixture= 50.0000
V_fixture= 0.0
V_fixture_min= 0.0
V_fixture_max= 0.0
|time   V(typ)   V(min)   V(max)
0s        676.3mV    366.6mV    959.6mV
1.117ns   677mV      366.5mV    938.4mV
1.259ns   677.9mV    366.5mV    798.4mV
1.536ns   640.6mV    366.7mV    120.1mV
1.837ns   278.8mV    367.2mV    8.012mV
1.968ns   92.84mV    367.6mV    4.215mV
2.139ns   19.75mV    367.4mV    5.221mV
2.534ns   2.191mV    322.3mV    1.455mV
3.354ns   690.3uV    3.138mV    428.4uV
20ns      96.45uV    59.46uV    133.2uV
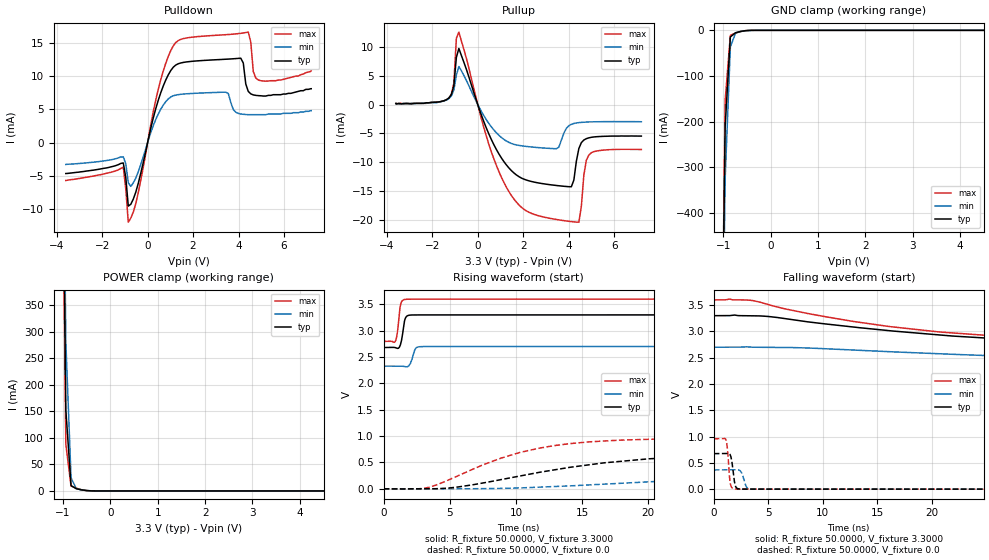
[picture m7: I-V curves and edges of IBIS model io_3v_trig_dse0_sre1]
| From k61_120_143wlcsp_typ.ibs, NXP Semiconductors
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[Model]  io_3v_trig_dse0_sre1
|   Model io_3v_trig_dse0_sre1
| Library cells for typ/min/max conditions are connected as defined below:
|  pad - External Pad
|  ipp_do_3v - Core Input
|  ipp_obe_3v - Output Buffer Enable
|  esd_boost - vdd_s_3v
|  esd_trigger - vss_s_3v
|  ipp_ame_3v - vss_s_3v
|  ipp_dse_3v - vss_s_3v
|  ipp_ina_3v - NC
|  ipp_ina_mux_3v - NC
|  ipp_ind_3v - NC
|  ipp_pue_3v - vss_s_3v
|  ipp_sre_3v - vdd_s_3v
|  tie_3v - vdd_s_3v
|  tie_hi - vdd_s_lv
|  vbuf_3v - vdd_s_3v
|  vdd_s_3v - vdd_s_3v
|  vdd_s_lv - vdd_s_lv
|  vss_bulk - vss_s_3v
|  vss_s_3v - vss_s_3v
| All other pins connected to ground
Model_type I/O
Polarity   Non-Inverting
Enable   Active-High
Vinl =   1.1550V
Vinh =   2.3100V
Vmeas =  1.6500V
Cref =   25.0000pF
Rref =   50.0000
Vref =   0.0V
C_comp   1.9033pF   1.7921pF   2.0562pF
[Temperature Range]   25.0000   0.1250k   -40.0000
[Voltage Range]   3.3000V   2.7000V   3.6000V
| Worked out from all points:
|   slope of the pulldown table from 0 to 0.495 V, typ, clamps not added: 74.6 ohm
|   slope of the pullup table from 0 to 0.495 V, typ, clamps not added: 96.1 ohm
|   GND clamp passes 1 mA (typ) near -0.54 V on its own axis
|   POWER clamp passes 1 mA (typ) near -0.53 V on its own axis
|   rising waveform, R_fixture 50.0000, V_fixture 3.3000: 20-80 % time 230ps typ, 285ps min, 205ps max; typ from 2.68 V to 3.3 V
|   rising waveform, R_fixture 50.0000, V_fixture 0.0: 20-80 % time 10.8ns typ, 20.7ns min, 6.55ns max; typ from 0 V to 0.676 V
|   falling waveform, R_fixture 50.0000, V_fixture 3.3000: 20-80 % time 22ns typ, 33.7ns min, 16.6ns max; typ from 3.3 V to 2.68 V
|   falling waveform, R_fixture 50.0000, V_fixture 0.0: 20-80 % time 255ps typ, 344ps min, 215ps max; typ from 0.676 V to 0 V
[Pulldown]
|Voltage   I(typ)   I(min)   I(max)
-3.6V     -4.64mA    -3.27mA    -5.68mA
-1.07V    -3.05mA    -2.138mA   -3.686mA
-850mV    -9.531mA   -6.04mA    -11.94mA
-520mV    -7.433mA   -5.304mA   -9.157mA
580mV     7.512mA    5.028mA    9.473mA
1.46V     11.97mA    7.259mA    15.51mA
3.44V     12.53mA    7.579mA    16.21mA
4.1V      12.68mA    4.3mA      16.42mA
4.43V     7.69mA     4.2mA      16.6mA
4.65V     7.17mA     4.2mA      10.69mA
4.87V     7.06mA     4.2mA      9.41mA
7.2V      8.1mA      4.8mA      10.8mA
[Pullup]
|Voltage   I(typ)   I(min)   I(max)
-3.6V     200uA      100uA      200uA
-1.27V    1.12mA     1.01mA     1.13mA
-1.05V    3.27mA     2.54mA     3.696mA
-940mV    8.16mA     5.079mA    11.47mA
-830mV    9.694mA    6.562mA    12.52mA
1.15V     -9.866mA   -6.026mA   -13.47mA
3.24V     -13.9mA    -7.608mA   -19.73mA
4.12V     -14.22mA   -3.42mA    -20.25mA
4.45V     -7.608mA   -3.13mA    -20.35mA
4.78V     -5.902mA   -3.04mA    -9.632mA
5V        -5.67mA    -3mA       -8.343mA
7.2V      -5.46mA    -2.98mA    -7.78mA
[GND_clamp]
|Voltage   I(typ)   I(min)   I(max)
-3.6V     -47.82A    -47.1A     -48.34A
-1.07V    -1.102A    -1.183A    -1.105A
-960mV    -210.7mA   -326mA     -154mA
-850mV    -14.47mA   -36.11mA   -11.11mA
-740mV    -5.262mA   -6.035mA   -5.843mA
-520mV    -636.9uA   -916uA     -467.5uA
-300mV    -2.578uA   -18.15uA   -370.9nA
7.2V      0A         0A         0A
[POWER_clamp]
|Voltage   I(typ)   I(min)   I(max)
-3.6V     36.98A     36.74A     37.19A
-1.05V    1.02A      1.161A     949.9mA
-940mV    152.3mA    280.6mA    87.35mA
-830mV    9.987mA    24.48mA    9.181mA
-720mV    4.227mA    4.409mA    5.116mA
-500mV    628.6uA    744.4uA    622.6uA
-390mV    66.57uA    164.1uA    29.9uA
7.2V      0A         0A         0A
[Ramp]
| variable   typ   min   max
dV/dt_r  0.4058/10.7521n   0.2200/20.6470n   0.5758/6.5493n
dV/dt_f  0.3716/21.9741n   0.2235/33.6806n   0.4822/16.5904n
R_load = 50.0000
[Rising Waveform]
R_fixture= 50.0000
V_fixture= 3.3000
V_fixture_min= 2.7000
V_fixture_max= 3.6000
|time   V(typ)   V(min)   V(max)
0s        2.681V     2.328V     2.796V
873.9ps   2.679V     2.329V     2.794V
1.053ns   2.665V     2.329V     2.991V
1.187ns   2.687V     2.329V     3.332V
1.337ns   2.801V     2.328V     3.54V
1.603ns   3.21V      2.318V     3.593V
1.889ns   3.292V     2.332V     3.598V
2.437ns   3.299V     2.669V     3.599V
3.158ns   3.299V     2.699V     3.599V
250ns     3.3V       2.7V       3.6V
[Rising Waveform]
R_fixture= 50.0000
V_fixture= 0.0
V_fixture_min= 0.0
V_fixture_max= 0.0
|time   V(typ)   V(min)   V(max)
0s        5.332nV    489.5nV    4.027nV
3.401ns   -65.29uV   -90.68uV   27.26mV
5.422ns   27.57mV    22.03uV    224.8mV
8.79ns    170.4mV    7.225mV    576.4mV
11.64ns   306.7mV    29.41mV    765.9mV
15.55ns   456.4mV    73.77mV    891mV
20.44ns   574.6mV    138.4mV    942.2mV
38.5ns    671.9mV    308.8mV    959.4mV
54.43ns   676.1mV    353.3mV    959.5mV
250ns     676.3mV    366.6mV    959.6mV
[Falling Waveform]
R_fixture= 50.0000
V_fixture= 3.3000
V_fixture_min= 2.7000
V_fixture_max= 3.6000
|time   V(typ)   V(min)   V(max)
0s        3.3V       2.7V       3.6V
3.611ns   3.299V     2.7V       3.586V
7.348ns   3.219V     2.693V     3.395V
12.82ns   3.084V     2.645V     3.19V
20.67ns   2.934V     2.576V     2.991V
27.45ns   2.843V     2.523V     2.889V
39.99ns   2.737V     2.442V     2.817V
61.63ns   2.689V     2.364V     2.798V
86.63ns   2.682V     2.336V     2.796V
250ns     2.681V     2.328V     2.796V
[Falling Waveform]
R_fixture= 50.0000
V_fixture= 0.0
V_fixture_min= 0.0
V_fixture_max= 0.0
|time   V(typ)   V(min)   V(max)
0s        676.3mV    366.6mV    959.6mV
1.13ns    678mV      366.3mV    930.4mV
1.265ns   680.7mV    366.3mV    739.8mV
1.52ns    644.9mV    366.5mV    106.7mV
1.898ns   140.5mV    368.2mV    4.398mV
2.065ns   30.29mV    369.9mV    2.235mV
2.55ns    1.471mV    311.8mV    1.387mV
3.097ns   935uV      18.09mV    1.065mV
3.711ns   694.3uV    692.2uV    867.8uV
250ns     13.62nV    487.5nV    11.48nV
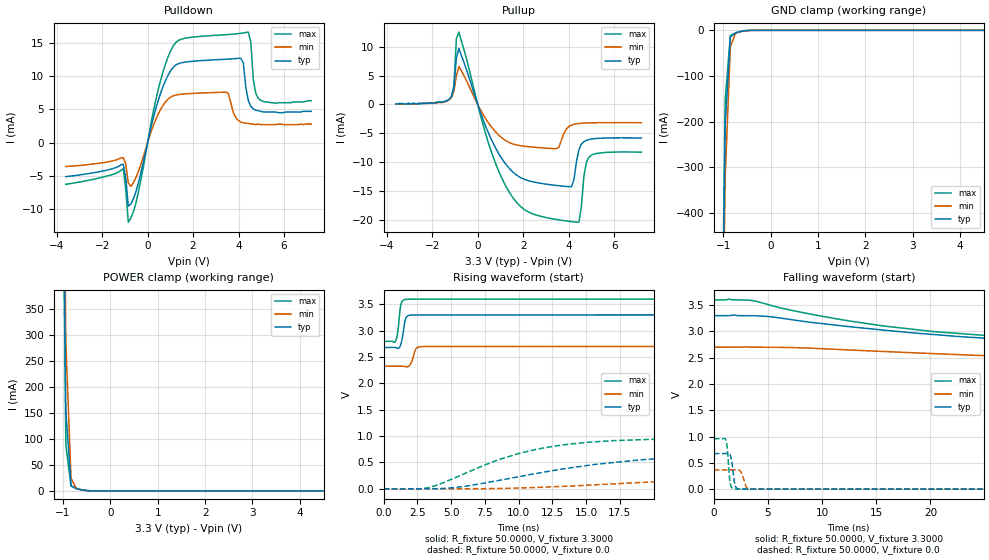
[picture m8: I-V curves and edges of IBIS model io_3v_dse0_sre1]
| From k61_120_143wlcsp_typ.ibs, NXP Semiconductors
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[Model]  io_3v_dse0_sre1
|   Model io_3v_dse0_sre1
| Library cells for typ/min/max conditions are connected as defined below:
|  pad - External Pad
|  ipp_do_3v - Core Input
|  ipp_obe_3v - Output Buffer Enable
|  esd_boost - vdd_s_3v
|  esd_trigger - vss_s_3v
|  ipp_ame_3v - vss_s_3v
|  ipp_dse_3v - vss_s_3v
|  ipp_ina_3v - NC
|  ipp_ina_mux_3v - NC
|  ipp_ind_3v - NC
|  ipp_pue_3v - vss_s_3v
|  ipp_sre_3v - vdd_s_3v
|  tie_3v - vdd_s_3v
|  tie_hi - vdd_s_lv
|  vbuf_3v - vdd_s_3v
|  vdd_s_3v - vdd_s_3v
|  vdd_s_lv - vdd_s_lv
|  vss_bulk - vss_s_3v
|  vss_s_3v - vss_s_3v
| All other pins connected to ground
Model_type I/O
Polarity   Non-Inverting
Enable   Active-High
Vinl =   1.1550V
Vinh =   2.3100V
Vmeas =  1.6500V
Cref =   25.0000pF
Rref =   50.0000
Vref =   0.0V
C_comp   1.9040pF   1.7928pF   2.0571pF
[Temperature Range]   25.0000   0.1250k   -40.0000
[Voltage Range]   3.3000V   2.7000V   3.6000V
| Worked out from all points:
|   slope of the pulldown table from 0 to 0.495 V, typ, clamps not added: 74.6 ohm
|   slope of the pullup table from 0 to 0.495 V, typ, clamps not added: 96.1 ohm
|   GND clamp passes 1 mA (typ) near -0.54 V on its own axis
|   POWER clamp passes 1 mA (typ) near -0.53 V on its own axis
|   rising waveform, R_fixture 50.0000, V_fixture 3.3000: 20-80 % time 232ps typ, 280ps min, 203ps max; typ from 2.68 V to 3.3 V
|   rising waveform, R_fixture 50.0000, V_fixture 0.0: 20-80 % time 10.6ns typ, 20.7ns min, 6.58ns max; typ from 0 V to 0.676 V
|   falling waveform, R_fixture 50.0000, V_fixture 3.3000: 20-80 % time 22.3ns typ, 33.7ns min, 16.6ns max; typ from 3.3 V to 2.68 V
|   falling waveform, R_fixture 50.0000, V_fixture 0.0: 20-80 % time 254ps typ, 347ps min, 212ps max; typ from 0.676 V to 0 V
[Pulldown]
|Voltage   I(typ)   I(min)   I(max)
-3.6V     -5.11mA    -3.58mA    -6.26mA
-1.07V    -3.221mA   -2.25mA    -3.914mA
-850mV    -9.536mA   -6.048mA   -11.95mA
-520mV    -7.435mA   -5.304mA   -9.159mA
580mV     7.513mA    5.028mA    9.475mA
1.46V     11.97mA    7.26mA     15.51mA
3.44V     12.53mA    7.58mA     16.21mA
4.1V      12.68mA    3.11mA     16.42mA
4.43V     6.32mA     2.9mA      16.6mA
4.65V     5.07mA     2.8mA      9.53mA
4.87V     4.8mA      2.8mA      6.66mA
7.2V      4.7mA      2.8mA      6.3mA
[Pullup]
|Voltage   I(typ)   I(min)   I(max)
-3.6V     100uA      100uA      100uA
-1.27V    830uA      760uA      820uA
-1.05V    2.86mA     2.26mA     3.17mA
-940mV    8.013mA    4.943mA    11.33mA
-830mV    9.687mA    6.548mA    12.52mA
710mV     -6.946mA   -4.399mA   -9.402mA
2.14V     -13.06mA   -7.25mA    -18.39mA
3.46V     -14mA      -7.642mA   -19.88mA
4.12V     -14.22mA   -3.569mA   -20.25mA
4.45V     -7.839mA   -3.29mA    -20.35mA
4.89V     -6.059mA   -3.18mA    -9.139mA
7.2V      -5.79mA    -3.15mA    -8.25mA
[GND_clamp]
|Voltage   I(typ)   I(min)   I(max)
-3.6V     -47.78A    -47.06A    -48.3A
-1.07V    -1.101A    -1.183A    -1.105A
-960mV    -210.7mA   -326mA     -154mA
-850mV    -14.47mA   -36.11mA   -11.11mA
-740mV    -5.262mA   -6.035mA   -5.843mA
-520mV    -637uA     -916uA     -467.5uA
-300mV    -2.578uA   -18.15uA   -370.9nA
7.2V      0A         0A         0A
[POWER_clamp]
|Voltage   I(typ)   I(min)   I(max)
-3.6V     52.51A     51.88A     52.98A
-1.05V    1.126A     1.265A     1.065A
-940mV    154.2mA    286.1mA    88.03mA
-830mV    9.989mA    24.5mA     9.181mA
-720mV    4.227mA    4.409mA    5.116mA
-390mV    66.57uA    164.1uA    29.9uA
7.2V      0A         0A         0A
[Ramp]
| variable   typ   min   max
dV/dt_r  0.4058/10.6214n   0.2200/20.7141n   0.5757/6.5774n
dV/dt_f  0.3717/22.2614n   0.2235/33.7057n   0.4823/16.5966n
R_load = 50.0000
[Rising Waveform]
R_fixture= 50.0000
V_fixture= 3.3000
V_fixture_min= 2.7000
V_fixture_max= 3.6000
|time   V(typ)   V(min)   V(max)
0s        2.681V     2.328V     2.796V
861.3ps   2.68V      2.329V     2.789V
1.013ns   2.667V     2.329V     2.924V
1.146ns   2.673V     2.329V     3.221V
1.341ns   2.809V     2.328V     3.542V
1.597ns   3.205V     2.318V     3.593V
1.926ns   3.294V     2.343V     3.598V
2.445ns   3.299V     2.671V     3.599V
3.167ns   3.299V     2.699V     3.599V
250ns     3.3V       2.7V       3.6V
[Rising Waveform]
R_fixture= 50.0000
V_fixture= 0.0
V_fixture_min= 0.0
V_fixture_max= 0.0
|time   V(typ)   V(min)   V(max)
0s        5.331nV    489.5nV    4.026nV
3.341ns   -72.51uV   -95.82uV   23.77mV
5.094ns   19mV       -25.01uV   188.3mV
8.601ns   161.6mV    6.488mV    560mV
12.62ns   348.9mV    39.3mV     809.2mV
17.02ns   498.4mV    92.49mV    913.8mV
22.1ns    599.9mV    160.2mV    948.6mV
39.4ns    672.1mV    313.2mV    959.4mV
55.29ns   676.1mV    354.3mV    959.5mV
250ns     676.3mV    366.6mV    959.6mV
[Falling Waveform]
R_fixture= 50.0000
V_fixture= 3.3000
V_fixture_min= 2.7000
V_fixture_max= 3.6000
|time   V(typ)   V(min)   V(max)
0s        3.3V       2.7V       3.6V
3.517ns   3.3V       2.7V       3.589V
7.042ns   3.228V     2.694V     3.408V
12.25ns   3.097V     2.651V     3.208V
20.29ns   2.942V     2.578V     2.998V
27.15ns   2.846V     2.523V     2.892V
39.62ns   2.741V     2.445V     2.818V
59.64ns   2.691V     2.368V     2.798V
84.64ns   2.682V     2.337V     2.796V
250ns     2.681V     2.328V     2.796V
[Falling Waveform]
R_fixture= 50.0000
V_fixture= 0.0
V_fixture_min= 0.0
V_fixture_max= 0.0
|time   V(typ)   V(min)   V(max)
0s        676.3mV    366.6mV    959.6mV
1.108ns   677.7mV    366.3mV    943.8mV
1.236ns   680mV      366.3mV    800.9mV
1.524ns   643.9mV    366.5mV    102.4mV
1.934ns   99.66mV    368.5mV    3.715mV
2.129ns   17.36mV    370mV      2.081mV
2.512ns   1.724mV    327.2mV    1.482mV
3.036ns   1.016mV    30.56mV    1.118mV
3.687ns   719.5uV    750.2uV    880.3uV
250ns     13.63nV    487.5nV    11.46nV
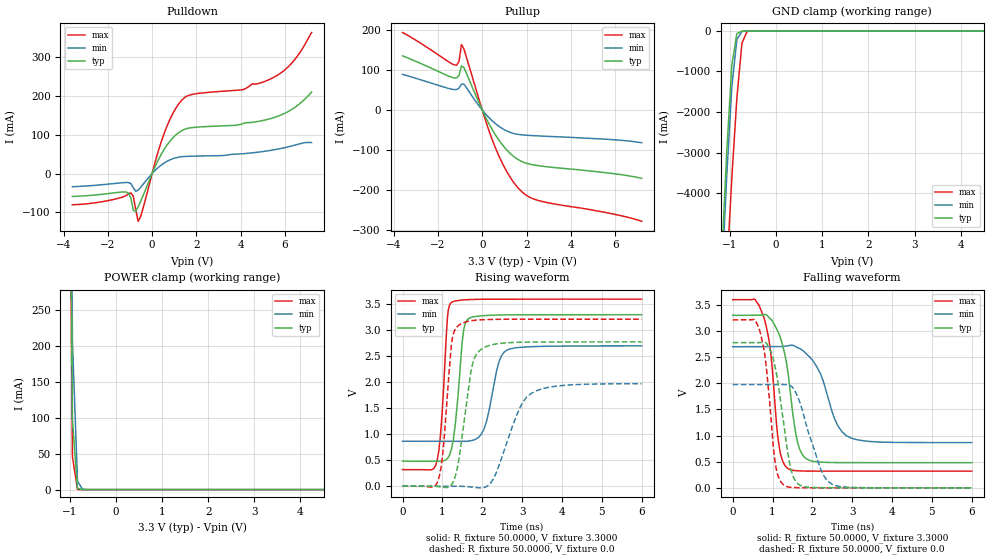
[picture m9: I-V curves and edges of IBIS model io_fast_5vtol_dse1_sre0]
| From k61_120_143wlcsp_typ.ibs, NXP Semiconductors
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[Model]  io_fast_5vtol_dse1_sre0
|   Model io_fast_5vtol_dse1_sre0
| Library cells for typ/min/max conditions are connected as defined below:
|  pad - External Pad
|  ipp_do - Core Input
|  ipp_obe - Output Buffer Enable
|  esd_boost - vdd_s_3v
|  esd_bus - vdd_s_3v
|  ipp_ame - vss_s_lv
|  ipp_dse - vdd_s_lv
|  ipp_ina40a_5vtol - NC
|  ipp_ina40b_5vtol - NC
|  ipp_ina_5vtol - NC
|  ipp_ina_mux_3v - NC
|  ipp_ind - NC
|  ipp_ind_3v - NC
|  ipp_pue - vss_s_lv
|  ipp_sre - vss_s_lv
|  tie_3v - vdd_s_3v
|  tie_hi - vdd_s_lv
|  vbuf_3v - vdd_s_3v
|  vdd_bulk_lv - vdd_s_lv
|  vdd_s_3v - vdd_s_3v
|  vdd_s_lv - vdd_s_lv
|  vss_bulk - vss_s_3v
|  vss_s_3v - vss_s_3v
|  vss_s_lv - vss_s_lv
| All other pins connected to ground
Model_type I/O
Polarity   Non-Inverting
Enable   Active-High
Vinl =   1.1550V
Vinh =   2.3100V
Vmeas =  1.6500V
Cref =   25.0000pF
Rref =   50.0000
Vref =   0.0V
C_comp   4.8302pF   4.6092pF   5.0790pF
[Temperature Range]   25.0000   0.1250k   -40.0000
[Voltage Range]   3.3000V   2.7000V   3.6000V
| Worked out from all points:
|   slope of the pulldown table from 0 to 0.495 V, typ, clamps not added: 8.59 ohm
|   slope of the pullup table from 0 to 0.495 V, typ, clamps not added: 9.33 ohm
|   GND clamp passes 1 mA (typ) near -0.54 V on its own axis
|   POWER clamp passes 1 mA (typ) near -0.79 V on its own axis
|   rising waveform, R_fixture 50.0000, V_fixture 3.3000: 20-80 % time 194ps typ, 298ps min, 150ps max; typ from 0.481 V to 3.3 V
|   rising waveform, R_fixture 50.0000, V_fixture 0.0: 20-80 % time 303ps typ, 570ps min, 197ps max; typ from 0 V to 2.78 V
|   falling waveform, R_fixture 50.0000, V_fixture 3.3000: 20-80 % time 332ps typ, 515ps min, 251ps max; typ from 3.3 V to 0.482 V
|   falling waveform, R_fixture 50.0000, V_fixture 0.0: 20-80 % time 317ps typ, 480ps min, 239ps max; typ from 2.78 V to 0 V
[Pulldown]
|Voltage   I(typ)   I(min)   I(max)
-3.6V     -59.22mA   -34.05mA   -80.5mA
-1.29V    -47.58mA   -23.54mA   -59.74mA
-960mV    -63.34mA   -25.9mA    -50.29mA
-850mV    -95.19mA   -36.87mA   -58.11mA
-630mV    -85.86mA   -42.95mA   -123.3mA
470mV     55.27mA    24.18mA    91.83mA
910mV     90.4mA     37.69mA    152.1mA
1.35V     111mA      43.43mA    189.9mA
4.1V      128.8mA    51.09mA    216.5mA
5.42V     142.9mA    60.4mA     246mA
6.41V     169.2mA    72.8mA     291.7mA
7.2V      210mA      79.7mA     363.7mA
[Pullup]
|Voltage   I(typ)   I(min)   I(max)
-3.6V     135.3mA    89.2mA     193.5mA
-1.27V    80.13mA    51.07mA    113mA
-1.16V    80.16mA    51.18mA    112.2mA
-1.05V    86.44mA    54.53mA    121mA
-940mV    110.2mA    64.63mA    163.6mA
-830mV    106.4mA    64.63mA    152.9mA
160mV     -18.66mA   -10.49mA   -28.08mA
710mV     -71.72mA   -38.88mA   -109.3mA
1.26V     -108.3mA   -55.73mA   -167.8mA
1.92V     -131.7mA   -62.58mA   -210.1mA
2.69V     -140.1mA   -65.06mA   -228.1mA
7.2V      -170.7mA   -81.67mA   -277.9mA
[GND_clamp]
|Voltage   I(typ)   I(min)   I(max)
-3.6V     -73.34A    -73.38A    -74.77A
-1.18V    -5.66A     -6.206A    -8.642A
-1.07V    -2.998A    -3.593A    -5.955A
-960mV    -859.3mA   -1.399A    -3.637A
-850mV    -67.61mA   -213.2mA   -1.663A
-740mV    -7.668mA   -16.88mA   -304.8mA
-630mV    -2.587mA   -2.229mA   -18.83mA
-520mV    -662.1uA   -532.3uA   -1.741mA
7.2V      0A         0A         0A
[POWER_clamp]
|Voltage   I(typ)   I(min)   I(max)
-3.6V     45.85A     45.45A     46.17A
-1.05V    1.004A     1.14A      941.6mA
-940mV    96.57mA    206.1mA    45.73mA
-830mV    1.646mA    11.48mA    218.1uA
-720mV    22.84uA    474.3uA    919.1nA
-610mV    316.6nA    19.24uA    4.178nA
7.2V      0A         0A         0A
[Ramp]
| variable   typ   min   max
dV/dt_r  1.6661/0.3026n   1.1836/0.5700n   1.9282/0.1974n
dV/dt_f  1.6910/0.3315n   1.1004/0.5155n   1.9683/0.2510n
R_load = 50.0000
[Rising Waveform]
R_fixture= 50.0000
V_fixture= 3.3000
V_fixture_min= 2.7000
V_fixture_max= 3.6000
|time   V(typ)   V(min)   V(max)
0s        481.4mV    865.4mV    319.2mV
869.4ps   478.5mV    865.4mV    498.7mV
984.4ps   484mV      865.4mV    1.301V
1.123ns   529.5mV    865.5mV    3.221V
1.232ns   730.8mV    865.8mV    3.538V
1.527ns   2.955V     862.6mV    3.584V
1.653ns   3.223V     868mV      3.59V
2.041ns   3.283V     1.093V     3.598V
2.63ns    3.297V     2.623V     3.599V
6ns       3.3V       2.699V     3.6V
[Rising Waveform]
R_fixture= 50.0000
V_fixture= 0.0
V_fixture_min= 0.0
V_fixture_max= 0.0
|time   V(typ)   V(min)   V(max)
0s        310.4pV    40.6nV     167.4pV
883.2ps   -6.264mV   -640.5nV   91.17mV
1.002ns   -17.66mV   -7.563uV   566.2mV
1.229ns   30.2mV     471.2uV    2.734V
1.43ns    598mV      -484.6uV   3.107V
1.762ns   2.37V      -18.37mV   3.188V
2.01ns    2.652V     -29.56mV   3.205V
2.281ns   2.727V     142.7mV    3.21V
3.231ns   2.774V     1.786V     3.213V
6ns       2.777V     1.973V     3.214V
[Falling Waveform]
R_fixture= 50.0000
V_fixture= 3.3000
V_fixture_min= 2.7000
V_fixture_max= 3.6000
|time   V(typ)   V(min)   V(max)
0s        3.3V       2.7V       3.6V
543.4ps   3.3V       2.7V       3.61V
800.6ps   3.315V     2.7V       3.22V
951.8ps   3.23V      2.7V       2.618V
1.168ns   2.937V     2.7V       774.1mV
1.394ns   2.171V     2.718V     365.3mV
1.635ns   853.2mV    2.679V     326.3mV
1.879ns   542.8mV    2.541V     321.2mV
2.853ns   482.7mV    1V         319.6mV
6ns       481.7mV    866.1mV    319.4mV
[Falling Waveform]
R_fixture= 50.0000
V_fixture= 0.0
V_fixture_min= 0.0
V_fixture_max= 0.0
|time   V(typ)   V(min)   V(max)
0s        2.777V     1.975V     3.214V
663.6ps   2.777V     1.975V     3.049V
824.9ps   2.779V     1.975V     2.442V
1.083ns   2.253V     1.974V     403.1mV
1.276ns   1.268V     1.978V     58.03mV
1.415ns   524.5mV    1.963V     12.27mV
1.583ns   123.4mV    1.823V     4.31mV
2.218ns   3.051mV    340.9mV    474.3uV
2.498ns   1.109mV    66.91mV    344.8uV
6ns       233.4uV    323.5uV    181.6uV
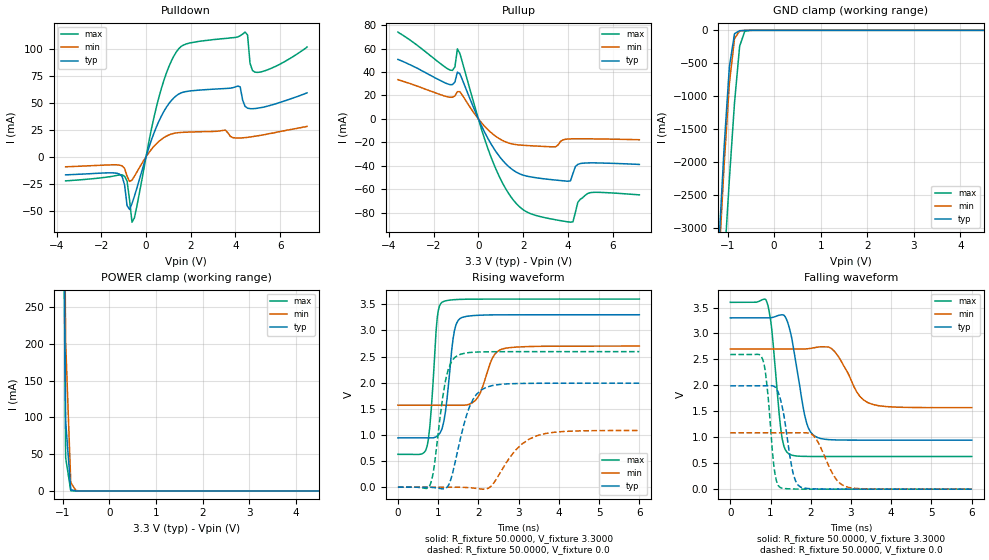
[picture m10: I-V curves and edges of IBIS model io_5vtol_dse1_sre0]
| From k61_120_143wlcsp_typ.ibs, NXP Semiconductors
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[Model]  io_5vtol_dse1_sre0
|   Model io_5vtol_dse1_sre0
| Library cells for typ/min/max conditions are connected as defined below:
|  pad - External Pad
|  ipp_do - Core Input
|  ipp_obe - Output Buffer Enable
|  esd_boost - vdd_s_3v
|  esd_bus - vdd_s_3v
|  ipp_ame - vss_s_lv
|  ipp_dse - vdd_s_lv
|  ipp_ina40a_5vtol - NC
|  ipp_ina40b_5vtol - NC
|  ipp_ina_5vtol - NC
|  ipp_ina_mux_3v - NC
|  ipp_ind - NC
|  ipp_ind_3v - NC
|  ipp_pue - vss_s_lv
|  ipp_sre - vss_s_lv
|  tie_3v - vdd_s_3v
|  tie_hi - vdd_s_lv
|  vbuf_3v - vdd_s_3v
|  vdd_bulk_lv - vdd_s_lv
|  vdd_s_3v - vdd_s_3v
|  vdd_s_lv - vdd_s_lv
|  vss_bulk - vss_s_3v
|  vss_s_3v - vss_s_3v
|  vss_s_lv - vss_s_lv
| All other pins connected to ground
Model_type I/O
Polarity   Non-Inverting
Enable   Active-High
Vinl =   1.1550V
Vinh =   2.3100V
Vmeas =  1.6500V
Cref =   25.0000pF
Rref =   50.0000
Vref =   0.0V
C_comp   2.9184pF   2.7887pF   3.0744pF
[Temperature Range]   25.0000   0.1250k   -40.0000
[Voltage Range]   3.3000V   2.7000V   3.6000V
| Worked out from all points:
|   slope of the pulldown table from 0 to 0.495 V, typ, clamps not added: 16.9 ohm
|   slope of the pullup table from 0 to 0.495 V, typ, clamps not added: 26 ohm
|   GND clamp passes 1 mA (typ) near -0.58 V on its own axis
|   POWER clamp passes 1 mA (typ) near -0.79 V on its own axis
|   rising waveform, R_fixture 50.0000, V_fixture 3.3000: 20-80 % time 194ps typ, 312ps min, 150ps max; typ from 0.944 V to 3.3 V
|   rising waveform, R_fixture 50.0000, V_fixture 0.0: 20-80 % time 413ps typ, 668ps min, 270ps max; typ from 0 V to 1.99 V
|   falling waveform, R_fixture 50.0000, V_fixture 3.3000: 20-80 % time 304ps typ, 463ps min, 205ps max; typ from 3.3 V to 0.944 V
|   falling waveform, R_fixture 50.0000, V_fixture 0.0: 20-80 % time 246ps typ, 404ps min, 172ps max; typ from 1.99 V to 0 V
[Pulldown]
|Voltage   I(typ)   I(min)   I(max)
-3.6V     -16.8mA    -9.34mA    -22.41mA
-960mV    -26.33mA   -10.88mA   -18.18mA
-850mV    -45.49mA   -18.02mA   -22.59mA
-630mV    -43.55mA   -21.69mA   -60.83mA
580mV     33.33mA    14.39mA    55.77mA
1.46V     58.28mA    22.44mA    100.4mA
4.1V      65.72mA    17.38mA    111.4mA
4.43V     46.8mA     17.8mA     115.9mA
4.54V     45.21mA    18mA       113.3mA
4.65V     44.72mA    18.4mA     86.87mA
4.98V     45.1mA     19.4mA     78.42mA
7.2V      59.4mA     28.2mA     102mA
[Pullup]
|Voltage   I(typ)   I(min)   I(max)
-3.6V     50.7mA     33.5mA     74mA
-1.27V    29.24mA    18.45mA    41.65mA
-1.05V    31.45mA    19.65mA    44.42mA
-940mV    39.86mA    23.21mA    59.68mA
710mV     -25.74mA   -13.86mA   -39.48mA
1.37V     -40.86mA   -20.62mA   -64.05mA
2.03V     -48.09mA   -22.5mA    -77.75mA
4.12V     -52.71mA   -17.02mA   -88mA
4.34V     -40.52mA   -16.93mA   -79.47mA
4.45V     -38.73mA   -16.91mA   -70.98mA
4.89V     -37.5mA    -16.96mA   -63.55mA
7.2V      -38.79mA   -17.73mA   -64.73mA
[GND_clamp]
|Voltage   I(typ)   I(min)   I(max)
-3.6V     -39.79A    -39.79A    -41.16A
-1.18V    -3.193A    -3.445A    -4.927A
-1.07V    -1.746A    -2.022A    -3.54A
-960mV    -554.7mA   -809.6mA   -2.265A
-850mV    -51.43mA   -127.1mA   -1.104A
-740mV    -5.185mA   -9.693mA   -242.4mA
-630mV    -1.474mA   -1.24mA    -14.98mA
-520mV    -384.8uA   -304.4uA   -1.148mA
7.2V      0A         0A         0A
[POWER_clamp]
|Voltage   I(typ)   I(min)   I(max)
-3.6V     45.62A     45.23A     45.93A
-1.05V    987.4mA    1.121A     927.4mA
-940mV    95.32mA    202.8mA    45.29mA
-830mV    1.645mA    11.46mA    218.1uA
-720mV    22.84uA    474.3uA    919.1nA
-610mV    316.6nA    19.24uA    4.178nA
7.2V      0A         0A         0A
[Ramp]
| variable   typ   min   max
dV/dt_r  1.1940/0.4135n   0.6509/0.6676n   1.5562/0.2701n
dV/dt_f  1.4135/0.3044n   0.6775/0.4628n   1.7827/0.2050n
R_load = 50.0000
[Rising Waveform]
R_fixture= 50.0000
V_fixture= 3.3000
V_fixture_min= 2.7000
V_fixture_max= 3.6000
|time   V(typ)   V(min)   V(max)
0s        943.7mV    1.569V     628.5mV
724.5ps   943.4mV    1.569V     779.7mV
823.1ps   942mV      1.569V     1.434V
976.5ps   979.3mV    1.569V     3.241V
1.103ns   1.136V     1.57V      3.542V
1.37ns    2.836V     1.569V     3.586V
1.544ns   3.227V     1.567V     3.594V
1.979ns   3.289V     1.71V      3.598V
2.611ns   3.298V     2.648V     3.599V
6ns       3.3V       2.7V       3.6V
[Rising Waveform]
R_fixture= 50.0000
V_fixture= 0.0
V_fixture_min= 0.0
V_fixture_max= 0.0
|time   V(typ)   V(min)   V(max)
0s        463.5pV    58.98nV    297.1pV
795.2ps   -734.3uV   845.9nV    39.33mV
908ps     -9.107mV   -9.336uV   430.8mV
1.198ns   -19.54mV   98.44uV    2.096V
1.479ns   680.5mV    277.1uV    2.518V
1.778ns   1.537V     -9.984mV   2.577V
2.193ns   1.91V      -34.94mV   2.591V
2.917ns   1.983V     702.9mV    2.593V
3.454ns   1.988V     983.9mV    2.593V
6ns       1.99V      1.085V     2.594V
[Falling Waveform]
R_fixture= 50.0000
V_fixture= 3.3000
V_fixture_min= 2.7000
V_fixture_max= 3.6000
|time   V(typ)   V(min)   V(max)
0s        3.3V       2.7V       3.6V
903.7ps   3.3V       2.7V       3.617V
1.031ns   3.306V     2.7V       3.088V
1.256ns   3.357V     2.7V       1.152V
1.451ns   3.154V     2.7V       683.1mV
1.848ns   1.429V     2.701V     631.5mV
2.109ns   1.019V     2.729V     630mV
2.55ns    950.3mV    2.687V     629.4mV
3.43ns    944.9mV    1.663V     629.1mV
6ns       944.2mV    1.571V     628.9mV
[Falling Waveform]
R_fixture= 50.0000
V_fixture= 0.0
V_fixture_min= 0.0
V_fixture_max= 0.0
|time   V(typ)   V(min)   V(max)
0s        1.991V     1.086V     2.594V
800.2ps   1.99V      1.086V     2.512V
915.4ps   1.991V     1.086V     1.972V
1.109ns   1.97V      1.086V     305mV
1.234ns   1.769V     1.086V     35.74mV
1.568ns   285.6mV    1.086V     3.22mV
1.746ns   41.1mV     1.087V     1.19mV
2.072ns   5.84mV     1.028V     601.1uV
2.836ns   555.3uV    59.66mV    396.1uV
6ns       285uV      267.4uV    259.4uV
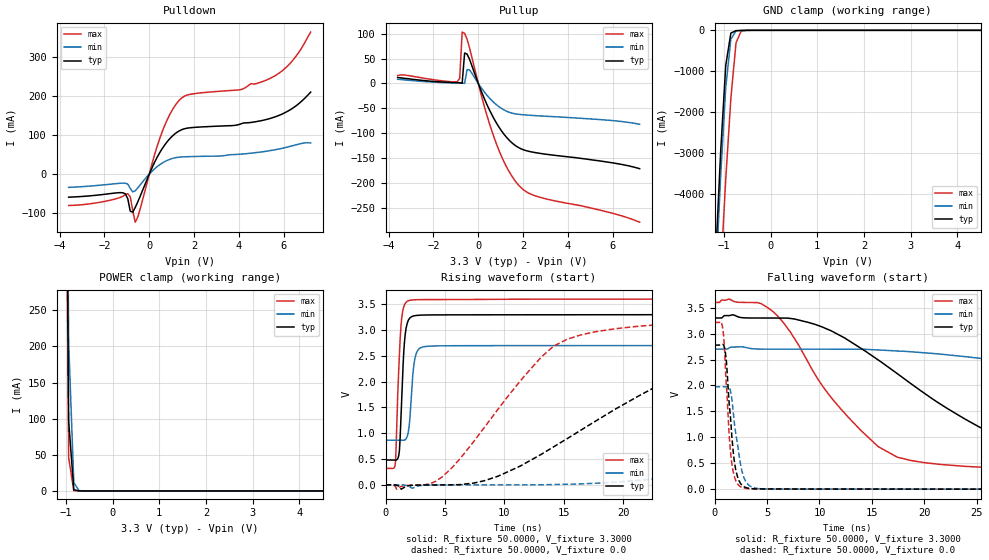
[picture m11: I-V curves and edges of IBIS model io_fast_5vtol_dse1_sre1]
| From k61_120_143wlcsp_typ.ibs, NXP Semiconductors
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[Model]  io_fast_5vtol_dse1_sre1
|   Model io_fast_5vtol_dse1_sre1
| Library cells for typ/min/max conditions are connected as defined below:
|  pad - External Pad
|  ipp_do - Core Input
|  ipp_obe - Output Buffer Enable
|  esd_boost - vdd_s_3v
|  esd_bus - vdd_s_3v
|  ipp_ame - vss_s_lv
|  ipp_dse - vdd_s_lv
|  ipp_ina40a_5vtol - NC
|  ipp_ina40b_5vtol - NC
|  ipp_ina_5vtol - NC
|  ipp_ina_mux_3v - NC
|  ipp_ind - NC
|  ipp_ind_3v - NC
|  ipp_pue - vss_s_lv
|  ipp_sre - vdd_s_lv
|  tie_3v - vdd_s_3v
|  tie_hi - vdd_s_lv
|  vbuf_3v - vdd_s_3v
|  vdd_bulk_lv - vdd_s_lv
|  vdd_s_3v - vdd_s_3v
|  vdd_s_lv - vdd_s_lv
|  vss_bulk - vss_s_3v
|  vss_s_3v - vss_s_3v
|  vss_s_lv - vss_s_lv
| All other pins connected to ground
Model_type I/O
Polarity   Non-Inverting
Enable   Active-High
Vinl =   1.1550V
Vinh =   2.3100V
Vmeas =  1.6500V
Cref =   25.0000pF
Rref =   50.0000
Vref =   0.0V
C_comp   4.8302pF   4.6092pF   5.0790pF
[Temperature Range]   25.0000   0.1250k   -40.0000
[Voltage Range]   3.3000V   2.7000V   3.6000V
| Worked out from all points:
|   slope of the pulldown table from 0 to 0.495 V, typ, clamps not added: 8.59 ohm
|   slope of the pullup table from 0 to 0.495 V, typ, clamps not added: 9.33 ohm
|   GND clamp passes 1 mA (typ) near -0.54 V on its own axis
|   POWER clamp passes 1 mA (typ) near -0.79 V on its own axis
|   rising waveform, R_fixture 50.0000, V_fixture 3.3000: 20-80 % time 330ps typ, 367ps min, 337ps max; typ from 0.481 V to 3.3 V
|   rising waveform, R_fixture 50.0000, V_fixture 0.0: 20-80 % time 12.9ns typ, 32.6ns min, 6.83ns max; typ from 0 V to 2.78 V
|   falling waveform, R_fixture 50.0000, V_fixture 3.3000: 20-80 % time 13ns typ, 33.6ns min, 7.28ns max; typ from 3.3 V to 0.481 V
|   falling waveform, R_fixture 50.0000, V_fixture 0.0: 20-80 % time 660ps typ, 823ps min, 576ps max; typ from 2.78 V to 0 V
[Pulldown]
|Voltage   I(typ)   I(min)   I(max)
-3.6V     -59.22mA   -34.05mA   -80.5mA
-1.29V    -47.58mA   -23.54mA   -59.74mA
-960mV    -63.34mA   -25.9mA    -50.29mA
-850mV    -95.19mA   -36.87mA   -58.11mA
-630mV    -85.86mA   -42.94mA   -123.3mA
470mV     55.27mA    24.18mA    91.83mA
910mV     90.4mA     37.69mA    152.1mA
1.35V     111mA      43.42mA    189.9mA
4.1V      128.8mA    51.09mA    216.5mA
5.42V     142.9mA    60.4mA     246mA
6.41V     169.2mA    72.8mA     291.7mA
7.2V      210mA      79.7mA     363.7mA
[Pullup]
|Voltage   I(typ)   I(min)   I(max)
-3.6V     12.1mA     8.5mA      16mA
-940mV    1.771mA    1.197mA    3.465mA
-830mV    1.246mA    965.8uA    10.48mA
-720mV    725.2uA    615.5uA    103.4mA
-610mV    61.29mA    315.5uA    100.8mA
-500mV    58.99mA    28.06mA    88.99mA
-390mV    48.58mA    27.33mA    71.55mA
710mV     -71.72mA   -38.87mA   -109.3mA
1.26V     -108.3mA   -55.73mA   -167.8mA
1.81V     -129.2mA   -62.08mA   -205.1mA
2.69V     -140.1mA   -65.06mA   -228.1mA
7.2V      -171.4mA   -82.05mA   -279mA
[GND_clamp]
|Voltage   I(typ)   I(min)   I(max)
-3.6V     -73.34A    -73.38A    -74.77A
-1.18V    -5.66A     -6.206A    -8.642A
-1.07V    -2.998A    -3.593A    -5.955A
-960mV    -859.3mA   -1.399A    -3.637A
-850mV    -67.61mA   -213.2mA   -1.663A
-740mV    -7.668mA   -16.88mA   -304.8mA
-630mV    -2.587mA   -2.229mA   -18.83mA
-520mV    -662.1uA   -532.3uA   -1.741mA
7.2V      0A         0A         0A
[POWER_clamp]
|Voltage   I(typ)   I(min)   I(max)
-3.6V     45.85A     45.45A     46.17A
-1.05V    1.004A     1.14A      941.6mA
-940mV    96.57mA    206.1mA    45.73mA
-830mV    1.646mA    11.48mA    218.1uA
-720mV    22.84uA    474.3uA    919.1nA
-610mV    316.6nA    19.24uA    4.178nA
7.2V      0A         0A         0A
[Ramp]
| variable   typ   min   max
dV/dt_r  1.6664/12.8984n   1.1847/32.5666n   1.9284/6.8253n
dV/dt_f  1.6912/13.0232n   1.0995/33.6289n   1.9685/7.2848n
R_load = 50.0000
[Rising Waveform]
R_fixture= 50.0000
V_fixture= 3.3000
V_fixture_min= 2.7000
V_fixture_max= 3.6000
|time   V(typ)   V(min)   V(max)
0s        481.4mV    865.4mV    319.2mV
804.4ps   480mV      865.4mV    380.1mV
883.2ps   479.6mV    865.4mV    656.5mV
1.123ns   578.1mV    865.5mV    2.286V
1.34ns    1.567V     865.1mV    3.188V
1.653ns   2.908V     873.3mV    3.511V
1.986ns   3.213V     1.127V     3.573V
2.468ns   3.278V     2.436V     3.587V
5.664ns   3.294V     2.696V     3.591V
250ns     3.3V       2.7V       3.6V
[Rising Waveform]
R_fixture= 50.0000
V_fixture= 0.0
V_fixture_min= 0.0
V_fixture_max= 0.0
|time   V(typ)   V(min)   V(max)
0s        310.4pV    40.6nV     167.4pV
4.748ns   -2.75mV    -1.233mV   150.2mV
9.436ns   163.1mV    -1.09mV    1.455V
14.12ns   731.3mV    5.561mV    2.684V
24.04ns   2.046V     155.2mV    3.119V
30.08ns   2.455V     350.2mV    3.169V
39.13ns   2.638V     720.8mV    3.199V
58.87ns   2.746V     1.463V     3.212V
81.07ns   2.771V     1.808V     3.214V
250ns     2.777V     1.974V     3.214V
[Falling Waveform]
R_fixture= 50.0000
V_fixture= 3.3000
V_fixture_min= 2.7000
V_fixture_max= 3.6000
|time   V(typ)   V(min)   V(max)
0s        3.3V       2.7V       3.6V
5.581ns   3.3V       2.7V       3.422V
10.9ns    3.072V     2.7V       1.822V
15.59ns   2.491V     2.684V     820.2mV
23.83ns   1.357V     2.557V     440.3mV
29.21ns   877.6mV    2.423V     394.4mV
36.64ns   684mV      2.186V     361.4mV
58.49ns   540.5mV    1.387V     329.9mV
77.16ns   506.9mV    1.1V       322.7mV
250ns     481.4mV    867.5mV    319.2mV
[Falling Waveform]
R_fixture= 50.0000
V_fixture= 0.0
V_fixture_min= 0.0
V_fixture_max= 0.0
|time   V(typ)   V(min)   V(max)
0s        2.777V     1.975V     3.214V
807.6ps   2.788V     1.975V     3.063V
930.9ps   2.739V     1.975V     2.791V
1.131ns   2.464V     1.975V     1.992V
1.442ns   1.563V     1.947V     911.8mV
1.743ns   800.9mV    1.573V     371mV
2.011ns   383mV      1.086V     169.9mV
2.47ns    111.7mV    485.8mV    49.03mV
3.234ns   17.76mV    84.96mV    9.441mV
250ns     -258.3nV   3.583uV    -973.4pV
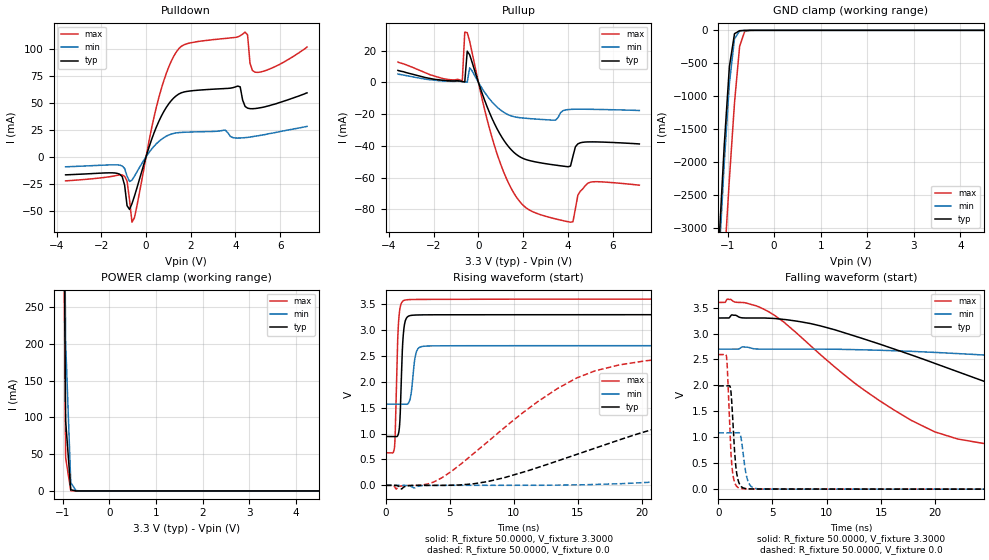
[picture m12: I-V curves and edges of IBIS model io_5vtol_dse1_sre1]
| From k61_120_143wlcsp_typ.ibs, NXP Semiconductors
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[Model]  io_5vtol_dse1_sre1
|   Model io_5vtol_dse1_sre1
| Library cells for typ/min/max conditions are connected as defined below:
|  pad - External Pad
|  ipp_do - Core Input
|  ipp_obe - Output Buffer Enable
|  esd_boost - vdd_s_3v
|  esd_bus - vdd_s_3v
|  ipp_ame - vss_s_lv
|  ipp_dse - vdd_s_lv
|  ipp_ina40a_5vtol - NC
|  ipp_ina40b_5vtol - NC
|  ipp_ina_5vtol - NC
|  ipp_ina_mux_3v - NC
|  ipp_ind - NC
|  ipp_ind_3v - NC
|  ipp_pue - vss_s_lv
|  ipp_sre - vdd_s_lv
|  tie_3v - vdd_s_3v
|  tie_hi - vdd_s_lv
|  vbuf_3v - vdd_s_3v
|  vdd_bulk_lv - vdd_s_lv
|  vdd_s_3v - vdd_s_3v
|  vdd_s_lv - vdd_s_lv
|  vss_bulk - vss_s_3v
|  vss_s_3v - vss_s_3v
|  vss_s_lv - vss_s_lv
| All other pins connected to ground
Model_type I/O
Polarity   Non-Inverting
Enable   Active-High
Vinl =   1.1550V
Vinh =   2.3100V
Vmeas =  1.6500V
Cref =   25.0000pF
Rref =   50.0000
Vref =   0.0V
C_comp   2.9184pF   2.7887pF   3.0744pF
[Temperature Range]   25.0000   0.1250k   -40.0000
[Voltage Range]   3.3000V   2.7000V   3.6000V
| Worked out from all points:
|   slope of the pulldown table from 0 to 0.495 V, typ, clamps not added: 16.9 ohm
|   slope of the pullup table from 0 to 0.495 V, typ, clamps not added: 26 ohm
|   GND clamp passes 1 mA (typ) near -0.58 V on its own axis
|   POWER clamp passes 1 mA (typ) near -0.79 V on its own axis
|   rising waveform, R_fixture 50.0000, V_fixture 3.3000: 20-80 % time 211ps typ, 298ps min, 203ps max; typ from 0.944 V to 3.3 V
|   rising waveform, R_fixture 50.0000, V_fixture 0.0: 20-80 % time 17ns typ, 37.9ns min, 8.52ns max; typ from 0 V to 1.99 V
|   falling waveform, R_fixture 50.0000, V_fixture 3.3000: 20-80 % time 20.9ns typ, 49ns min, 11.6ns max; typ from 3.3 V to 0.944 V
|   falling waveform, R_fixture 50.0000, V_fixture 0.0: 20-80 % time 374ps typ, 459ps min, 338ps max; typ from 1.99 V to 0 V
[Pulldown]
|Voltage   I(typ)   I(min)   I(max)
-3.6V     -16.8mA    -9.34mA    -22.41mA
-960mV    -26.33mA   -10.88mA   -18.18mA
-850mV    -45.49mA   -18.02mA   -22.59mA
-630mV    -43.55mA   -21.69mA   -60.83mA
580mV     33.33mA    14.38mA    55.77mA
1.46V     58.28mA    22.44mA    100.4mA
4.1V      65.72mA    17.38mA    111.4mA
4.43V     46.8mA     17.8mA     115.9mA
4.54V     45.21mA    18mA       113.3mA
4.65V     44.72mA    18.3mA     86.87mA
4.98V     45.1mA     19.4mA     78.42mA
7.2V      59.4mA     28.2mA     102mA
[Pullup]
|Voltage   I(typ)   I(min)   I(max)
-3.6V     7.5mA      5.3mA      12.8mA
-720mV    488.7uA    417.1uA    955.4uA
-610mV    254.6uA    229.7uA    31.62mA
-500mV    19.62mA    105.2uA    31.26mA
-390mV    17.3mA     9.141mA    25.82mA
930mV     -31.69mA   -16.76mA   -48.93mA
2.36V     -49.48mA   -22.89mA   -80.94mA
4.01V     -53.11mA   -17.13mA   -87.72mA
4.23V     -46.46mA   -16.95mA   -87.7mA
4.45V     -38.72mA   -16.91mA   -70.98mA
4.89V     -37.49mA   -16.95mA   -63.55mA
7.2V      -38.77mA   -17.72mA   -64.69mA
[GND_clamp]
|Voltage   I(typ)   I(min)   I(max)
-3.6V     -39.79A    -39.79A    -41.16A
-1.18V    -3.193A    -3.445A    -4.927A
-1.07V    -1.746A    -2.022A    -3.54A
-960mV    -554.7mA   -809.6mA   -2.265A
-850mV    -51.43mA   -127.1mA   -1.104A
-740mV    -5.185mA   -9.693mA   -242.4mA
-630mV    -1.474mA   -1.24mA    -14.98mA
-520mV    -384.8uA   -304.4uA   -1.148mA
7.2V      0A         0A         0A
[POWER_clamp]
|Voltage   I(typ)   I(min)   I(max)
-3.6V     45.62A     45.23A     45.93A
-1.05V    987.4mA    1.121A     927.4mA
-940mV    95.32mA    202.8mA    45.29mA
-830mV    1.645mA    11.46mA    218.1uA
-720mV    22.84uA    474.3uA    919.1nA
-610mV    316.6nA    19.24uA    4.178nA
7.2V      0A         0A         0A
[Ramp]
| variable   typ   min   max
dV/dt_r  1.1944/16.9607n   0.6514/37.9142n   1.5565/8.5237n
dV/dt_f  1.4137/20.9177n   0.6761/49.0337n   1.7829/11.5577n
R_load = 50.0000
[Rising Waveform]
R_fixture= 50.0000
V_fixture= 3.3000
V_fixture_min= 2.7000
V_fixture_max= 3.6000
|time   V(typ)   V(min)   V(max)
0s        943.7mV    1.569V     628.5mV
672.4ps   943.6mV    1.569V     727.5mV
730.8ps   943mV      1.569V     992.6mV
922ps     957.4mV    1.569V     2.802V
1.015ns   1.034V     1.57V      3.23V
1.403ns   3.017V     1.568V     3.573V
1.878ns   3.28V      1.655V     3.591V
2.429ns   3.292V     2.606V     3.593V
3.824ns   3.296V     2.696V     3.595V
250ns     3.3V       2.7V       3.6V
[Rising Waveform]
R_fixture= 50.0000
V_fixture= 0.0
V_fixture_min= 0.0
V_fixture_max= 0.0
|time   V(typ)   V(min)   V(max)
0s        463.5pV    58.98nV    297.1pV
806.7ps   -1.022mV   656.8nV    -74.28mV
4.371ns   -995.7uV   -467.9uV   144.3mV
11.9ns    345.9mV    937.6uV    1.622V
16.34ns   719.7mV    16.84mV    2.211V
27.48ns   1.502V     172.7mV    2.533V
35.99ns   1.792V     355.6mV    2.577V
45.85ns   1.911V     564.6mV    2.59V
88.04ns   1.989V     1.003V     2.594V
250ns     1.991V     1.086V     2.594V
[Falling Waveform]
R_fixture= 50.0000
V_fixture= 3.3000
V_fixture_min= 2.7000
V_fixture_max= 3.6000
|time   V(typ)   V(min)   V(max)
0s        3.3V       2.7V       3.6V
1.167ns   3.346V     2.7V       3.658V
4.627ns   3.297V     2.7V       3.425V
13.47ns   2.893V     2.686V     1.907V
19.95ns   2.426V     2.637V     1.106V
29.47ns   1.722V     2.52V      788.1mV
43.19ns   1.219V     2.289V     690.3mV
66.87ns   1.031V     1.919V     645.1mV
122.5ns   953.7mV    1.648V     629.3mV
250ns     943.8mV    1.573V     628.5mV
[Falling Waveform]
R_fixture= 50.0000
V_fixture= 0.0
V_fixture_min= 0.0
V_fixture_max= 0.0
|time   V(typ)   V(min)   V(max)
0s        1.991V     1.086V     2.594V
771.4ps   1.99V      1.086V     2.547V
1.148ns   1.93V      1.086V     794.2mV
1.405ns   1.102V     1.086V     219.1mV
1.806ns   193.9mV    1.089V     35mV
2.115ns   51.76mV    978.1mV    11.61mV
2.469ns   13.31mV    413.8mV    5.343mV
3.059ns   3.753mV    48.14mV    3.831mV
4.463ns   2.239mV    1.509mV    3.177mV
250ns     53.71nV    681.8nV    1.908nV
